VERSION 5.7 ;
BUSBITCHARS "[]" ;
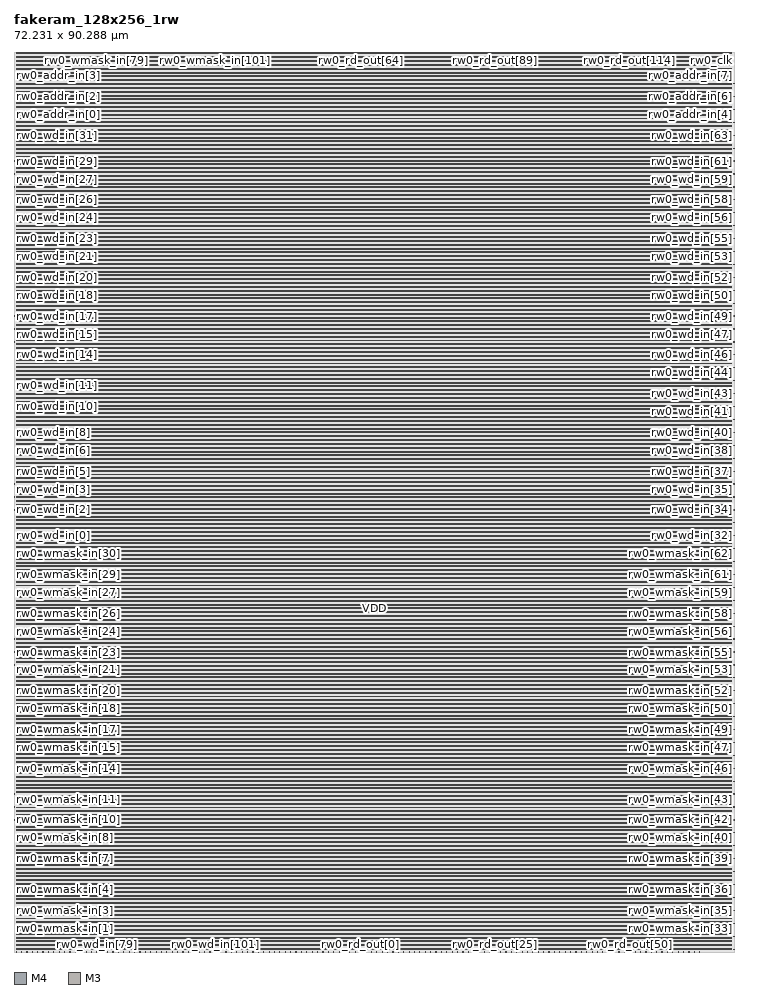
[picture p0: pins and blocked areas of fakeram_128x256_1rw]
MACRO fakeram_128x256_1rw
  FOREIGN fakeram_128x256_1rw 0 0 ;
  SYMMETRY X Y R90 ;
  SIZE 72.231 BY 90.288 ;
  CLASS BLOCK ;
  PIN rw0_wmask_in[0]
    DIRECTION INPUT ;
    USE SIGNAL ;
    SHAPE ABUTMENT ;
    PORT
      LAYER M4 ;
      RECT 0.000 0.276 0.072 0.300 ;
    END
  END rw0_wmask_in[0]
  PIN rw0_wmask_in[1]
    DIRECTION INPUT ;
    USE SIGNAL ;
    SHAPE ABUTMENT ;
    PORT
      LAYER M4 ;
      RECT 0.000 1.572 0.072 1.596 ;
    END
  END rw0_wmask_in[1]
  PIN rw0_wmask_in[2]
    DIRECTION INPUT ;
    USE SIGNAL ;
    SHAPE ABUTMENT ;
    PORT
      LAYER M4 ;
      RECT 0.000 2.868 0.072 2.892 ;
    END
  END rw0_wmask_in[2]
  PIN rw0_wmask_in[3]
    DIRECTION INPUT ;
    USE SIGNAL ;
    SHAPE ABUTMENT ;
    PORT
      LAYER M4 ;
      RECT 0.000 4.164 0.072 4.188 ;
    END
  END rw0_wmask_in[3]
  PIN rw0_wmask_in[4]
    DIRECTION INPUT ;
    USE SIGNAL ;
    SHAPE ABUTMENT ;
    PORT
      LAYER M4 ;
      RECT 0.000 5.460 0.072 5.484 ;
    END
  END rw0_wmask_in[4]
  PIN rw0_wmask_in[5]
    DIRECTION INPUT ;
    USE SIGNAL ;
    SHAPE ABUTMENT ;
    PORT
      LAYER M4 ;
      RECT 0.000 6.756 0.072 6.780 ;
    END
  END rw0_wmask_in[5]
  PIN rw0_wmask_in[6]
    DIRECTION INPUT ;
    USE SIGNAL ;
    SHAPE ABUTMENT ;
    PORT
      LAYER M4 ;
      RECT 0.000 8.052 0.072 8.076 ;
    END
  END rw0_wmask_in[6]
  PIN rw0_wmask_in[7]
    DIRECTION INPUT ;
    USE SIGNAL ;
    SHAPE ABUTMENT ;
    PORT
      LAYER M4 ;
      RECT 0.000 9.348 0.072 9.372 ;
    END
  END rw0_wmask_in[7]
  PIN rw0_wmask_in[8]
    DIRECTION INPUT ;
    USE SIGNAL ;
    SHAPE ABUTMENT ;
    PORT
      LAYER M4 ;
      RECT 0.000 10.644 0.072 10.668 ;
    END
  END rw0_wmask_in[8]
  PIN rw0_wmask_in[9]
    DIRECTION INPUT ;
    USE SIGNAL ;
    SHAPE ABUTMENT ;
    PORT
      LAYER M4 ;
      RECT 0.000 11.940 0.072 11.964 ;
    END
  END rw0_wmask_in[9]
  PIN rw0_wmask_in[10]
    DIRECTION INPUT ;
    USE SIGNAL ;
    SHAPE ABUTMENT ;
    PORT
      LAYER M4 ;
      RECT 0.000 13.236 0.072 13.260 ;
    END
  END rw0_wmask_in[10]
  PIN rw0_wmask_in[11]
    DIRECTION INPUT ;
    USE SIGNAL ;
    SHAPE ABUTMENT ;
    PORT
      LAYER M4 ;
      RECT 0.000 14.532 0.072 14.556 ;
    END
  END rw0_wmask_in[11]
  PIN rw0_wmask_in[12]
    DIRECTION INPUT ;
    USE SIGNAL ;
    SHAPE ABUTMENT ;
    PORT
      LAYER M4 ;
      RECT 0.000 15.828 0.072 15.852 ;
    END
  END rw0_wmask_in[12]
  PIN rw0_wmask_in[13]
    DIRECTION INPUT ;
    USE SIGNAL ;
    SHAPE ABUTMENT ;
    PORT
      LAYER M4 ;
      RECT 0.000 17.124 0.072 17.148 ;
    END
  END rw0_wmask_in[13]
  PIN rw0_wmask_in[14]
    DIRECTION INPUT ;
    USE SIGNAL ;
    SHAPE ABUTMENT ;
    PORT
      LAYER M4 ;
      RECT 0.000 18.420 0.072 18.444 ;
    END
  END rw0_wmask_in[14]
  PIN rw0_wmask_in[15]
    DIRECTION INPUT ;
    USE SIGNAL ;
    SHAPE ABUTMENT ;
    PORT
      LAYER M4 ;
      RECT 0.000 19.716 0.072 19.740 ;
    END
  END rw0_wmask_in[15]
  PIN rw0_wmask_in[16]
    DIRECTION INPUT ;
    USE SIGNAL ;
    SHAPE ABUTMENT ;
    PORT
      LAYER M4 ;
      RECT 0.000 21.012 0.072 21.036 ;
    END
  END rw0_wmask_in[16]
  PIN rw0_wmask_in[17]
    DIRECTION INPUT ;
    USE SIGNAL ;
    SHAPE ABUTMENT ;
    PORT
      LAYER M4 ;
      RECT 0.000 22.308 0.072 22.332 ;
    END
  END rw0_wmask_in[17]
  PIN rw0_wmask_in[18]
    DIRECTION INPUT ;
    USE SIGNAL ;
    SHAPE ABUTMENT ;
    PORT
      LAYER M4 ;
      RECT 0.000 23.604 0.072 23.628 ;
    END
  END rw0_wmask_in[18]
  PIN rw0_wmask_in[19]
    DIRECTION INPUT ;
    USE SIGNAL ;
    SHAPE ABUTMENT ;
    PORT
      LAYER M4 ;
      RECT 0.000 24.900 0.072 24.924 ;
    END
  END rw0_wmask_in[19]
  PIN rw0_wmask_in[20]
    DIRECTION INPUT ;
    USE SIGNAL ;
    SHAPE ABUTMENT ;
    PORT
      LAYER M4 ;
      RECT 0.000 26.196 0.072 26.220 ;
    END
  END rw0_wmask_in[20]
  PIN rw0_wmask_in[21]
    DIRECTION INPUT ;
    USE SIGNAL ;
    SHAPE ABUTMENT ;
    PORT
      LAYER M4 ;
      RECT 0.000 27.492 0.072 27.516 ;
    END
  END rw0_wmask_in[21]
  PIN rw0_wmask_in[22]
    DIRECTION INPUT ;
    USE SIGNAL ;
    SHAPE ABUTMENT ;
    PORT
      LAYER M4 ;
      RECT 0.000 28.788 0.072 28.812 ;
    END
  END rw0_wmask_in[22]
  PIN rw0_wmask_in[23]
    DIRECTION INPUT ;
    USE SIGNAL ;
    SHAPE ABUTMENT ;
    PORT
      LAYER M4 ;
      RECT 0.000 30.084 0.072 30.108 ;
    END
  END rw0_wmask_in[23]
  PIN rw0_wmask_in[24]
    DIRECTION INPUT ;
    USE SIGNAL ;
    SHAPE ABUTMENT ;
    PORT
      LAYER M4 ;
      RECT 0.000 31.380 0.072 31.404 ;
    END
  END rw0_wmask_in[24]
  PIN rw0_wmask_in[25]
    DIRECTION INPUT ;
    USE SIGNAL ;
    SHAPE ABUTMENT ;
    PORT
      LAYER M4 ;
      RECT 0.000 32.676 0.072 32.700 ;
    END
  END rw0_wmask_in[25]
  PIN rw0_wmask_in[26]
    DIRECTION INPUT ;
    USE SIGNAL ;
    SHAPE ABUTMENT ;
    PORT
      LAYER M4 ;
      RECT 0.000 33.972 0.072 33.996 ;
    END
  END rw0_wmask_in[26]
  PIN rw0_wmask_in[27]
    DIRECTION INPUT ;
    USE SIGNAL ;
    SHAPE ABUTMENT ;
    PORT
      LAYER M4 ;
      RECT 0.000 35.268 0.072 35.292 ;
    END
  END rw0_wmask_in[27]
  PIN rw0_wmask_in[28]
    DIRECTION INPUT ;
    USE SIGNAL ;
    SHAPE ABUTMENT ;
    PORT
      LAYER M4 ;
      RECT 0.000 36.564 0.072 36.588 ;
    END
  END rw0_wmask_in[28]
  PIN rw0_wmask_in[29]
    DIRECTION INPUT ;
    USE SIGNAL ;
    SHAPE ABUTMENT ;
    PORT
      LAYER M4 ;
      RECT 0.000 37.860 0.072 37.884 ;
    END
  END rw0_wmask_in[29]
  PIN rw0_wmask_in[30]
    DIRECTION INPUT ;
    USE SIGNAL ;
    SHAPE ABUTMENT ;
    PORT
      LAYER M4 ;
      RECT 0.000 39.156 0.072 39.180 ;
    END
  END rw0_wmask_in[30]
  PIN rw0_wmask_in[31]
    DIRECTION INPUT ;
    USE SIGNAL ;
    SHAPE ABUTMENT ;
    PORT
      LAYER M4 ;
      RECT 0.000 40.452 0.072 40.476 ;
    END
  END rw0_wmask_in[31]
  PIN rw0_wmask_in[32]
    DIRECTION INPUT ;
    USE SIGNAL ;
    SHAPE ABUTMENT ;
    PORT
      LAYER M4 ;
      RECT 72.159 0.276 72.231 0.300 ;
    END
  END rw0_wmask_in[32]
  PIN rw0_wmask_in[33]
    DIRECTION INPUT ;
    USE SIGNAL ;
    SHAPE ABUTMENT ;
    PORT
      LAYER M4 ;
      RECT 72.159 1.572 72.231 1.596 ;
    END
  END rw0_wmask_in[33]
  PIN rw0_wmask_in[34]
    DIRECTION INPUT ;
    USE SIGNAL ;
    SHAPE ABUTMENT ;
    PORT
      LAYER M4 ;
      RECT 72.159 2.868 72.231 2.892 ;
    END
  END rw0_wmask_in[34]
  PIN rw0_wmask_in[35]
    DIRECTION INPUT ;
    USE SIGNAL ;
    SHAPE ABUTMENT ;
    PORT
      LAYER M4 ;
      RECT 72.159 4.164 72.231 4.188 ;
    END
  END rw0_wmask_in[35]
  PIN rw0_wmask_in[36]
    DIRECTION INPUT ;
    USE SIGNAL ;
    SHAPE ABUTMENT ;
    PORT
      LAYER M4 ;
      RECT 72.159 5.460 72.231 5.484 ;
    END
  END rw0_wmask_in[36]
  PIN rw0_wmask_in[37]
    DIRECTION INPUT ;
    USE SIGNAL ;
    SHAPE ABUTMENT ;
    PORT
      LAYER M4 ;
      RECT 72.159 6.756 72.231 6.780 ;
    END
  END rw0_wmask_in[37]
  PIN rw0_wmask_in[38]
    DIRECTION INPUT ;
    USE SIGNAL ;
    SHAPE ABUTMENT ;
    PORT
      LAYER M4 ;
      RECT 72.159 8.052 72.231 8.076 ;
    END
  END rw0_wmask_in[38]
  PIN rw0_wmask_in[39]
    DIRECTION INPUT ;
    USE SIGNAL ;
    SHAPE ABUTMENT ;
    PORT
      LAYER M4 ;
      RECT 72.159 9.348 72.231 9.372 ;
    END
  END rw0_wmask_in[39]
  PIN rw0_wmask_in[40]
    DIRECTION INPUT ;
    USE SIGNAL ;
    SHAPE ABUTMENT ;
    PORT
      LAYER M4 ;
      RECT 72.159 10.644 72.231 10.668 ;
    END
  END rw0_wmask_in[40]
  PIN rw0_wmask_in[41]
    DIRECTION INPUT ;
    USE SIGNAL ;
    SHAPE ABUTMENT ;
    PORT
      LAYER M4 ;
      RECT 72.159 11.940 72.231 11.964 ;
    END
  END rw0_wmask_in[41]
  PIN rw0_wmask_in[42]
    DIRECTION INPUT ;
    USE SIGNAL ;
    SHAPE ABUTMENT ;
    PORT
      LAYER M4 ;
      RECT 72.159 13.236 72.231 13.260 ;
    END
  END rw0_wmask_in[42]
  PIN rw0_wmask_in[43]
    DIRECTION INPUT ;
    USE SIGNAL ;
    SHAPE ABUTMENT ;
    PORT
      LAYER M4 ;
      RECT 72.159 14.532 72.231 14.556 ;
    END
  END rw0_wmask_in[43]
  PIN rw0_wmask_in[44]
    DIRECTION INPUT ;
    USE SIGNAL ;
    SHAPE ABUTMENT ;
    PORT
      LAYER M4 ;
      RECT 72.159 15.828 72.231 15.852 ;
    END
  END rw0_wmask_in[44]
  PIN rw0_wmask_in[45]
    DIRECTION INPUT ;
    USE SIGNAL ;
    SHAPE ABUTMENT ;
    PORT
      LAYER M4 ;
      RECT 72.159 17.124 72.231 17.148 ;
    END
  END rw0_wmask_in[45]
  PIN rw0_wmask_in[46]
    DIRECTION INPUT ;
    USE SIGNAL ;
    SHAPE ABUTMENT ;
    PORT
      LAYER M4 ;
      RECT 72.159 18.420 72.231 18.444 ;
    END
  END rw0_wmask_in[46]
  PIN rw0_wmask_in[47]
    DIRECTION INPUT ;
    USE SIGNAL ;
    SHAPE ABUTMENT ;
    PORT
      LAYER M4 ;
      RECT 72.159 19.716 72.231 19.740 ;
    END
  END rw0_wmask_in[47]
  PIN rw0_wmask_in[48]
    DIRECTION INPUT ;
    USE SIGNAL ;
    SHAPE ABUTMENT ;
    PORT
      LAYER M4 ;
      RECT 72.159 21.012 72.231 21.036 ;
    END
  END rw0_wmask_in[48]
  PIN rw0_wmask_in[49]
    DIRECTION INPUT ;
    USE SIGNAL ;
    SHAPE ABUTMENT ;
    PORT
      LAYER M4 ;
      RECT 72.159 22.308 72.231 22.332 ;
    END
  END rw0_wmask_in[49]
  PIN rw0_wmask_in[50]
    DIRECTION INPUT ;
    USE SIGNAL ;
    SHAPE ABUTMENT ;
    PORT
      LAYER M4 ;
      RECT 72.159 23.604 72.231 23.628 ;
    END
  END rw0_wmask_in[50]
  PIN rw0_wmask_in[51]
    DIRECTION INPUT ;
    USE SIGNAL ;
    SHAPE ABUTMENT ;
    PORT
      LAYER M4 ;
      RECT 72.159 24.900 72.231 24.924 ;
    END
  END rw0_wmask_in[51]
  PIN rw0_wmask_in[52]
    DIRECTION INPUT ;
    USE SIGNAL ;
    SHAPE ABUTMENT ;
    PORT
      LAYER M4 ;
      RECT 72.159 26.196 72.231 26.220 ;
    END
  END rw0_wmask_in[52]
  PIN rw0_wmask_in[53]
    DIRECTION INPUT ;
    USE SIGNAL ;
    SHAPE ABUTMENT ;
    PORT
      LAYER M4 ;
      RECT 72.159 27.492 72.231 27.516 ;
    END
  END rw0_wmask_in[53]
  PIN rw0_wmask_in[54]
    DIRECTION INPUT ;
    USE SIGNAL ;
    SHAPE ABUTMENT ;
    PORT
      LAYER M4 ;
      RECT 72.159 28.788 72.231 28.812 ;
    END
  END rw0_wmask_in[54]
  PIN rw0_wmask_in[55]
    DIRECTION INPUT ;
    USE SIGNAL ;
    SHAPE ABUTMENT ;
    PORT
      LAYER M4 ;
      RECT 72.159 30.084 72.231 30.108 ;
    END
  END rw0_wmask_in[55]
  PIN rw0_wmask_in[56]
    DIRECTION INPUT ;
    USE SIGNAL ;
    SHAPE ABUTMENT ;
    PORT
      LAYER M4 ;
      RECT 72.159 31.380 72.231 31.404 ;
    END
  END rw0_wmask_in[56]
  PIN rw0_wmask_in[57]
    DIRECTION INPUT ;
    USE SIGNAL ;
    SHAPE ABUTMENT ;
    PORT
      LAYER M4 ;
      RECT 72.159 32.676 72.231 32.700 ;
    END
  END rw0_wmask_in[57]
  PIN rw0_wmask_in[58]
    DIRECTION INPUT ;
    USE SIGNAL ;
    SHAPE ABUTMENT ;
    PORT
      LAYER M4 ;
      RECT 72.159 33.972 72.231 33.996 ;
    END
  END rw0_wmask_in[58]
  PIN rw0_wmask_in[59]
    DIRECTION INPUT ;
    USE SIGNAL ;
    SHAPE ABUTMENT ;
    PORT
      LAYER M4 ;
      RECT 72.159 35.268 72.231 35.292 ;
    END
  END rw0_wmask_in[59]
  PIN rw0_wmask_in[60]
    DIRECTION INPUT ;
    USE SIGNAL ;
    SHAPE ABUTMENT ;
    PORT
      LAYER M4 ;
      RECT 72.159 36.564 72.231 36.588 ;
    END
  END rw0_wmask_in[60]
  PIN rw0_wmask_in[61]
    DIRECTION INPUT ;
    USE SIGNAL ;
    SHAPE ABUTMENT ;
    PORT
      LAYER M4 ;
      RECT 72.159 37.860 72.231 37.884 ;
    END
  END rw0_wmask_in[61]
  PIN rw0_wmask_in[62]
    DIRECTION INPUT ;
    USE SIGNAL ;
    SHAPE ABUTMENT ;
    PORT
      LAYER M4 ;
      RECT 72.159 39.156 72.231 39.180 ;
    END
  END rw0_wmask_in[62]
  PIN rw0_wmask_in[63]
    DIRECTION INPUT ;
    USE SIGNAL ;
    SHAPE ABUTMENT ;
    PORT
      LAYER M4 ;
      RECT 72.159 40.452 72.231 40.476 ;
    END
  END rw0_wmask_in[63]
  PIN rw0_wmask_in[64]
    DIRECTION INPUT ;
    USE SIGNAL ;
    SHAPE ABUTMENT ;
    PORT
      LAYER M3 ;
      RECT 0.207 90.234 0.225 90.288 ;
    END
  END rw0_wmask_in[64]
  PIN rw0_wmask_in[65]
    DIRECTION INPUT ;
    USE SIGNAL ;
    SHAPE ABUTMENT ;
    PORT
      LAYER M3 ;
      RECT 0.747 90.234 0.765 90.288 ;
    END
  END rw0_wmask_in[65]
  PIN rw0_wmask_in[66]
    DIRECTION INPUT ;
    USE SIGNAL ;
    SHAPE ABUTMENT ;
    PORT
      LAYER M3 ;
      RECT 1.287 90.234 1.305 90.288 ;
    END
  END rw0_wmask_in[66]
  PIN rw0_wmask_in[67]
    DIRECTION INPUT ;
    USE SIGNAL ;
    SHAPE ABUTMENT ;
    PORT
      LAYER M3 ;
      RECT 1.827 90.234 1.845 90.288 ;
    END
  END rw0_wmask_in[67]
  PIN rw0_wmask_in[68]
    DIRECTION INPUT ;
    USE SIGNAL ;
    SHAPE ABUTMENT ;
    PORT
      LAYER M3 ;
      RECT 2.367 90.234 2.385 90.288 ;
    END
  END rw0_wmask_in[68]
  PIN rw0_wmask_in[69]
    DIRECTION INPUT ;
    USE SIGNAL ;
    SHAPE ABUTMENT ;
    PORT
      LAYER M3 ;
      RECT 2.907 90.234 2.925 90.288 ;
    END
  END rw0_wmask_in[69]
  PIN rw0_wmask_in[70]
    DIRECTION INPUT ;
    USE SIGNAL ;
    SHAPE ABUTMENT ;
    PORT
      LAYER M3 ;
      RECT 3.447 90.234 3.465 90.288 ;
    END
  END rw0_wmask_in[70]
  PIN rw0_wmask_in[71]
    DIRECTION INPUT ;
    USE SIGNAL ;
    SHAPE ABUTMENT ;
    PORT
      LAYER M3 ;
      RECT 3.987 90.234 4.005 90.288 ;
    END
  END rw0_wmask_in[71]
  PIN rw0_wmask_in[72]
    DIRECTION INPUT ;
    USE SIGNAL ;
    SHAPE ABUTMENT ;
    PORT
      LAYER M3 ;
      RECT 4.527 90.234 4.545 90.288 ;
    END
  END rw0_wmask_in[72]
  PIN rw0_wmask_in[73]
    DIRECTION INPUT ;
    USE SIGNAL ;
    SHAPE ABUTMENT ;
    PORT
      LAYER M3 ;
      RECT 5.067 90.234 5.085 90.288 ;
    END
  END rw0_wmask_in[73]
  PIN rw0_wmask_in[74]
    DIRECTION INPUT ;
    USE SIGNAL ;
    SHAPE ABUTMENT ;
    PORT
      LAYER M3 ;
      RECT 5.607 90.234 5.625 90.288 ;
    END
  END rw0_wmask_in[74]
  PIN rw0_wmask_in[75]
    DIRECTION INPUT ;
    USE SIGNAL ;
    SHAPE ABUTMENT ;
    PORT
      LAYER M3 ;
      RECT 6.147 90.234 6.165 90.288 ;
    END
  END rw0_wmask_in[75]
  PIN rw0_wmask_in[76]
    DIRECTION INPUT ;
    USE SIGNAL ;
    SHAPE ABUTMENT ;
    PORT
      LAYER M3 ;
      RECT 6.687 90.234 6.705 90.288 ;
    END
  END rw0_wmask_in[76]
  PIN rw0_wmask_in[77]
    DIRECTION INPUT ;
    USE SIGNAL ;
    SHAPE ABUTMENT ;
    PORT
      LAYER M3 ;
      RECT 7.227 90.234 7.245 90.288 ;
    END
  END rw0_wmask_in[77]
  PIN rw0_wmask_in[78]
    DIRECTION INPUT ;
    USE SIGNAL ;
    SHAPE ABUTMENT ;
    PORT
      LAYER M3 ;
      RECT 7.767 90.234 7.785 90.288 ;
    END
  END rw0_wmask_in[78]
  PIN rw0_wmask_in[79]
    DIRECTION INPUT ;
    USE SIGNAL ;
    SHAPE ABUTMENT ;
    PORT
      LAYER M3 ;
      RECT 8.307 90.234 8.325 90.288 ;
    END
  END rw0_wmask_in[79]
  PIN rw0_wmask_in[80]
    DIRECTION INPUT ;
    USE SIGNAL ;
    SHAPE ABUTMENT ;
    PORT
      LAYER M3 ;
      RECT 8.847 90.234 8.865 90.288 ;
    END
  END rw0_wmask_in[80]
  PIN rw0_wmask_in[81]
    DIRECTION INPUT ;
    USE SIGNAL ;
    SHAPE ABUTMENT ;
    PORT
      LAYER M3 ;
      RECT 9.387 90.234 9.405 90.288 ;
    END
  END rw0_wmask_in[81]
  PIN rw0_wmask_in[82]
    DIRECTION INPUT ;
    USE SIGNAL ;
    SHAPE ABUTMENT ;
    PORT
      LAYER M3 ;
      RECT 9.927 90.234 9.945 90.288 ;
    END
  END rw0_wmask_in[82]
  PIN rw0_wmask_in[83]
    DIRECTION INPUT ;
    USE SIGNAL ;
    SHAPE ABUTMENT ;
    PORT
      LAYER M3 ;
      RECT 10.467 90.234 10.485 90.288 ;
    END
  END rw0_wmask_in[83]
  PIN rw0_wmask_in[84]
    DIRECTION INPUT ;
    USE SIGNAL ;
    SHAPE ABUTMENT ;
    PORT
      LAYER M3 ;
      RECT 11.007 90.234 11.025 90.288 ;
    END
  END rw0_wmask_in[84]
  PIN rw0_wmask_in[85]
    DIRECTION INPUT ;
    USE SIGNAL ;
    SHAPE ABUTMENT ;
    PORT
      LAYER M3 ;
      RECT 11.547 90.234 11.565 90.288 ;
    END
  END rw0_wmask_in[85]
  PIN rw0_wmask_in[86]
    DIRECTION INPUT ;
    USE SIGNAL ;
    SHAPE ABUTMENT ;
    PORT
      LAYER M3 ;
      RECT 12.087 90.234 12.105 90.288 ;
    END
  END rw0_wmask_in[86]
  PIN rw0_wmask_in[87]
    DIRECTION INPUT ;
    USE SIGNAL ;
    SHAPE ABUTMENT ;
    PORT
      LAYER M3 ;
      RECT 12.627 90.234 12.645 90.288 ;
    END
  END rw0_wmask_in[87]
  PIN rw0_wmask_in[88]
    DIRECTION INPUT ;
    USE SIGNAL ;
    SHAPE ABUTMENT ;
    PORT
      LAYER M3 ;
      RECT 13.167 90.234 13.185 90.288 ;
    END
  END rw0_wmask_in[88]
  PIN rw0_wmask_in[89]
    DIRECTION INPUT ;
    USE SIGNAL ;
    SHAPE ABUTMENT ;
    PORT
      LAYER M3 ;
      RECT 13.707 90.234 13.725 90.288 ;
    END
  END rw0_wmask_in[89]
  PIN rw0_wmask_in[90]
    DIRECTION INPUT ;
    USE SIGNAL ;
    SHAPE ABUTMENT ;
    PORT
      LAYER M3 ;
      RECT 14.247 90.234 14.265 90.288 ;
    END
  END rw0_wmask_in[90]
  PIN rw0_wmask_in[91]
    DIRECTION INPUT ;
    USE SIGNAL ;
    SHAPE ABUTMENT ;
    PORT
      LAYER M3 ;
      RECT 14.787 90.234 14.805 90.288 ;
    END
  END rw0_wmask_in[91]
  PIN rw0_wmask_in[92]
    DIRECTION INPUT ;
    USE SIGNAL ;
    SHAPE ABUTMENT ;
    PORT
      LAYER M3 ;
      RECT 15.327 90.234 15.345 90.288 ;
    END
  END rw0_wmask_in[92]
  PIN rw0_wmask_in[93]
    DIRECTION INPUT ;
    USE SIGNAL ;
    SHAPE ABUTMENT ;
    PORT
      LAYER M3 ;
      RECT 15.867 90.234 15.885 90.288 ;
    END
  END rw0_wmask_in[93]
  PIN rw0_wmask_in[94]
    DIRECTION INPUT ;
    USE SIGNAL ;
    SHAPE ABUTMENT ;
    PORT
      LAYER M3 ;
      RECT 16.407 90.234 16.425 90.288 ;
    END
  END rw0_wmask_in[94]
  PIN rw0_wmask_in[95]
    DIRECTION INPUT ;
    USE SIGNAL ;
    SHAPE ABUTMENT ;
    PORT
      LAYER M3 ;
      RECT 16.947 90.234 16.965 90.288 ;
    END
  END rw0_wmask_in[95]
  PIN rw0_wmask_in[96]
    DIRECTION INPUT ;
    USE SIGNAL ;
    SHAPE ABUTMENT ;
    PORT
      LAYER M3 ;
      RECT 17.487 90.234 17.505 90.288 ;
    END
  END rw0_wmask_in[96]
  PIN rw0_wmask_in[97]
    DIRECTION INPUT ;
    USE SIGNAL ;
    SHAPE ABUTMENT ;
    PORT
      LAYER M3 ;
      RECT 18.027 90.234 18.045 90.288 ;
    END
  END rw0_wmask_in[97]
  PIN rw0_wmask_in[98]
    DIRECTION INPUT ;
    USE SIGNAL ;
    SHAPE ABUTMENT ;
    PORT
      LAYER M3 ;
      RECT 18.567 90.234 18.585 90.288 ;
    END
  END rw0_wmask_in[98]
  PIN rw0_wmask_in[99]
    DIRECTION INPUT ;
    USE SIGNAL ;
    SHAPE ABUTMENT ;
    PORT
      LAYER M3 ;
      RECT 19.107 90.234 19.125 90.288 ;
    END
  END rw0_wmask_in[99]
  PIN rw0_wmask_in[100]
    DIRECTION INPUT ;
    USE SIGNAL ;
    SHAPE ABUTMENT ;
    PORT
      LAYER M3 ;
      RECT 19.647 90.234 19.665 90.288 ;
    END
  END rw0_wmask_in[100]
  PIN rw0_wmask_in[101]
    DIRECTION INPUT ;
    USE SIGNAL ;
    SHAPE ABUTMENT ;
    PORT
      LAYER M3 ;
      RECT 20.187 90.234 20.205 90.288 ;
    END
  END rw0_wmask_in[101]
  PIN rw0_wmask_in[102]
    DIRECTION INPUT ;
    USE SIGNAL ;
    SHAPE ABUTMENT ;
    PORT
      LAYER M3 ;
      RECT 20.727 90.234 20.745 90.288 ;
    END
  END rw0_wmask_in[102]
  PIN rw0_wmask_in[103]
    DIRECTION INPUT ;
    USE SIGNAL ;
    SHAPE ABUTMENT ;
    PORT
      LAYER M3 ;
      RECT 21.267 90.234 21.285 90.288 ;
    END
  END rw0_wmask_in[103]
  PIN rw0_wmask_in[104]
    DIRECTION INPUT ;
    USE SIGNAL ;
    SHAPE ABUTMENT ;
    PORT
      LAYER M3 ;
      RECT 21.807 90.234 21.825 90.288 ;
    END
  END rw0_wmask_in[104]
  PIN rw0_wmask_in[105]
    DIRECTION INPUT ;
    USE SIGNAL ;
    SHAPE ABUTMENT ;
    PORT
      LAYER M3 ;
      RECT 22.347 90.234 22.365 90.288 ;
    END
  END rw0_wmask_in[105]
  PIN rw0_wmask_in[106]
    DIRECTION INPUT ;
    USE SIGNAL ;
    SHAPE ABUTMENT ;
    PORT
      LAYER M3 ;
      RECT 22.887 90.234 22.905 90.288 ;
    END
  END rw0_wmask_in[106]
  PIN rw0_wmask_in[107]
    DIRECTION INPUT ;
    USE SIGNAL ;
    SHAPE ABUTMENT ;
    PORT
      LAYER M3 ;
      RECT 23.427 90.234 23.445 90.288 ;
    END
  END rw0_wmask_in[107]
  PIN rw0_wmask_in[108]
    DIRECTION INPUT ;
    USE SIGNAL ;
    SHAPE ABUTMENT ;
    PORT
      LAYER M3 ;
      RECT 23.967 90.234 23.985 90.288 ;
    END
  END rw0_wmask_in[108]
  PIN rw0_wmask_in[109]
    DIRECTION INPUT ;
    USE SIGNAL ;
    SHAPE ABUTMENT ;
    PORT
      LAYER M3 ;
      RECT 24.507 90.234 24.525 90.288 ;
    END
  END rw0_wmask_in[109]
  PIN rw0_wmask_in[110]
    DIRECTION INPUT ;
    USE SIGNAL ;
    SHAPE ABUTMENT ;
    PORT
      LAYER M3 ;
      RECT 25.047 90.234 25.065 90.288 ;
    END
  END rw0_wmask_in[110]
  PIN rw0_wmask_in[111]
    DIRECTION INPUT ;
    USE SIGNAL ;
    SHAPE ABUTMENT ;
    PORT
      LAYER M3 ;
      RECT 25.587 90.234 25.605 90.288 ;
    END
  END rw0_wmask_in[111]
  PIN rw0_wmask_in[112]
    DIRECTION INPUT ;
    USE SIGNAL ;
    SHAPE ABUTMENT ;
    PORT
      LAYER M3 ;
      RECT 26.127 90.234 26.145 90.288 ;
    END
  END rw0_wmask_in[112]
  PIN rw0_wmask_in[113]
    DIRECTION INPUT ;
    USE SIGNAL ;
    SHAPE ABUTMENT ;
    PORT
      LAYER M3 ;
      RECT 26.667 90.234 26.685 90.288 ;
    END
  END rw0_wmask_in[113]
  PIN rw0_wmask_in[114]
    DIRECTION INPUT ;
    USE SIGNAL ;
    SHAPE ABUTMENT ;
    PORT
      LAYER M3 ;
      RECT 27.207 90.234 27.225 90.288 ;
    END
  END rw0_wmask_in[114]
  PIN rw0_wmask_in[115]
    DIRECTION INPUT ;
    USE SIGNAL ;
    SHAPE ABUTMENT ;
    PORT
      LAYER M3 ;
      RECT 27.747 90.234 27.765 90.288 ;
    END
  END rw0_wmask_in[115]
  PIN rw0_wmask_in[116]
    DIRECTION INPUT ;
    USE SIGNAL ;
    SHAPE ABUTMENT ;
    PORT
      LAYER M3 ;
      RECT 28.287 90.234 28.305 90.288 ;
    END
  END rw0_wmask_in[116]
  PIN rw0_wmask_in[117]
    DIRECTION INPUT ;
    USE SIGNAL ;
    SHAPE ABUTMENT ;
    PORT
      LAYER M3 ;
      RECT 28.827 90.234 28.845 90.288 ;
    END
  END rw0_wmask_in[117]
  PIN rw0_wmask_in[118]
    DIRECTION INPUT ;
    USE SIGNAL ;
    SHAPE ABUTMENT ;
    PORT
      LAYER M3 ;
      RECT 29.367 90.234 29.385 90.288 ;
    END
  END rw0_wmask_in[118]
  PIN rw0_wmask_in[119]
    DIRECTION INPUT ;
    USE SIGNAL ;
    SHAPE ABUTMENT ;
    PORT
      LAYER M3 ;
      RECT 29.907 90.234 29.925 90.288 ;
    END
  END rw0_wmask_in[119]
  PIN rw0_wmask_in[120]
    DIRECTION INPUT ;
    USE SIGNAL ;
    SHAPE ABUTMENT ;
    PORT
      LAYER M3 ;
      RECT 30.447 90.234 30.465 90.288 ;
    END
  END rw0_wmask_in[120]
  PIN rw0_wmask_in[121]
    DIRECTION INPUT ;
    USE SIGNAL ;
    SHAPE ABUTMENT ;
    PORT
      LAYER M3 ;
      RECT 30.987 90.234 31.005 90.288 ;
    END
  END rw0_wmask_in[121]
  PIN rw0_wmask_in[122]
    DIRECTION INPUT ;
    USE SIGNAL ;
    SHAPE ABUTMENT ;
    PORT
      LAYER M3 ;
      RECT 31.527 90.234 31.545 90.288 ;
    END
  END rw0_wmask_in[122]
  PIN rw0_wmask_in[123]
    DIRECTION INPUT ;
    USE SIGNAL ;
    SHAPE ABUTMENT ;
    PORT
      LAYER M3 ;
      RECT 32.067 90.234 32.085 90.288 ;
    END
  END rw0_wmask_in[123]
  PIN rw0_wmask_in[124]
    DIRECTION INPUT ;
    USE SIGNAL ;
    SHAPE ABUTMENT ;
    PORT
      LAYER M3 ;
      RECT 32.607 90.234 32.625 90.288 ;
    END
  END rw0_wmask_in[124]
  PIN rw0_wmask_in[125]
    DIRECTION INPUT ;
    USE SIGNAL ;
    SHAPE ABUTMENT ;
    PORT
      LAYER M3 ;
      RECT 33.147 90.234 33.165 90.288 ;
    END
  END rw0_wmask_in[125]
  PIN rw0_wmask_in[126]
    DIRECTION INPUT ;
    USE SIGNAL ;
    SHAPE ABUTMENT ;
    PORT
      LAYER M3 ;
      RECT 33.687 90.234 33.705 90.288 ;
    END
  END rw0_wmask_in[126]
  PIN rw0_wmask_in[127]
    DIRECTION INPUT ;
    USE SIGNAL ;
    SHAPE ABUTMENT ;
    PORT
      LAYER M3 ;
      RECT 34.227 90.234 34.245 90.288 ;
    END
  END rw0_wmask_in[127]
  PIN rw0_wd_in[0]
    DIRECTION INPUT ;
    USE SIGNAL ;
    SHAPE ABUTMENT ;
    PORT
      LAYER M4 ;
      RECT 0.000 41.748 0.072 41.772 ;
    END
  END rw0_wd_in[0]
  PIN rw0_wd_in[1]
    DIRECTION INPUT ;
    USE SIGNAL ;
    SHAPE ABUTMENT ;
    PORT
      LAYER M4 ;
      RECT 0.000 43.044 0.072 43.068 ;
    END
  END rw0_wd_in[1]
  PIN rw0_wd_in[2]
    DIRECTION INPUT ;
    USE SIGNAL ;
    SHAPE ABUTMENT ;
    PORT
      LAYER M4 ;
      RECT 0.000 44.340 0.072 44.364 ;
    END
  END rw0_wd_in[2]
  PIN rw0_wd_in[3]
    DIRECTION INPUT ;
    USE SIGNAL ;
    SHAPE ABUTMENT ;
    PORT
      LAYER M4 ;
      RECT 0.000 45.636 0.072 45.660 ;
    END
  END rw0_wd_in[3]
  PIN rw0_wd_in[4]
    DIRECTION INPUT ;
    USE SIGNAL ;
    SHAPE ABUTMENT ;
    PORT
      LAYER M4 ;
      RECT 0.000 46.932 0.072 46.956 ;
    END
  END rw0_wd_in[4]
  PIN rw0_wd_in[5]
    DIRECTION INPUT ;
    USE SIGNAL ;
    SHAPE ABUTMENT ;
    PORT
      LAYER M4 ;
      RECT 0.000 48.228 0.072 48.252 ;
    END
  END rw0_wd_in[5]
  PIN rw0_wd_in[6]
    DIRECTION INPUT ;
    USE SIGNAL ;
    SHAPE ABUTMENT ;
    PORT
      LAYER M4 ;
      RECT 0.000 49.524 0.072 49.548 ;
    END
  END rw0_wd_in[6]
  PIN rw0_wd_in[7]
    DIRECTION INPUT ;
    USE SIGNAL ;
    SHAPE ABUTMENT ;
    PORT
      LAYER M4 ;
      RECT 0.000 50.820 0.072 50.844 ;
    END
  END rw0_wd_in[7]
  PIN rw0_wd_in[8]
    DIRECTION INPUT ;
    USE SIGNAL ;
    SHAPE ABUTMENT ;
    PORT
      LAYER M4 ;
      RECT 0.000 52.116 0.072 52.140 ;
    END
  END rw0_wd_in[8]
  PIN rw0_wd_in[9]
    DIRECTION INPUT ;
    USE SIGNAL ;
    SHAPE ABUTMENT ;
    PORT
      LAYER M4 ;
      RECT 0.000 53.412 0.072 53.436 ;
    END
  END rw0_wd_in[9]
  PIN rw0_wd_in[10]
    DIRECTION INPUT ;
    USE SIGNAL ;
    SHAPE ABUTMENT ;
    PORT
      LAYER M4 ;
      RECT 0.000 54.708 0.072 54.732 ;
    END
  END rw0_wd_in[10]
  PIN rw0_wd_in[11]
    DIRECTION INPUT ;
    USE SIGNAL ;
    SHAPE ABUTMENT ;
    PORT
      LAYER M4 ;
      RECT 0.000 56.004 0.072 56.028 ;
    END
  END rw0_wd_in[11]
  PIN rw0_wd_in[12]
    DIRECTION INPUT ;
    USE SIGNAL ;
    SHAPE ABUTMENT ;
    PORT
      LAYER M4 ;
      RECT 0.000 57.300 0.072 57.324 ;
    END
  END rw0_wd_in[12]
  PIN rw0_wd_in[13]
    DIRECTION INPUT ;
    USE SIGNAL ;
    SHAPE ABUTMENT ;
    PORT
      LAYER M4 ;
      RECT 0.000 58.596 0.072 58.620 ;
    END
  END rw0_wd_in[13]
  PIN rw0_wd_in[14]
    DIRECTION INPUT ;
    USE SIGNAL ;
    SHAPE ABUTMENT ;
    PORT
      LAYER M4 ;
      RECT 0.000 59.892 0.072 59.916 ;
    END
  END rw0_wd_in[14]
  PIN rw0_wd_in[15]
    DIRECTION INPUT ;
    USE SIGNAL ;
    SHAPE ABUTMENT ;
    PORT
      LAYER M4 ;
      RECT 0.000 61.188 0.072 61.212 ;
    END
  END rw0_wd_in[15]
  PIN rw0_wd_in[16]
    DIRECTION INPUT ;
    USE SIGNAL ;
    SHAPE ABUTMENT ;
    PORT
      LAYER M4 ;
      RECT 0.000 62.484 0.072 62.508 ;
    END
  END rw0_wd_in[16]
  PIN rw0_wd_in[17]
    DIRECTION INPUT ;
    USE SIGNAL ;
    SHAPE ABUTMENT ;
    PORT
      LAYER M4 ;
      RECT 0.000 63.780 0.072 63.804 ;
    END
  END rw0_wd_in[17]
  PIN rw0_wd_in[18]
    DIRECTION INPUT ;
    USE SIGNAL ;
    SHAPE ABUTMENT ;
    PORT
      LAYER M4 ;
      RECT 0.000 65.076 0.072 65.100 ;
    END
  END rw0_wd_in[18]
  PIN rw0_wd_in[19]
    DIRECTION INPUT ;
    USE SIGNAL ;
    SHAPE ABUTMENT ;
    PORT
      LAYER M4 ;
      RECT 0.000 66.372 0.072 66.396 ;
    END
  END rw0_wd_in[19]
  PIN rw0_wd_in[20]
    DIRECTION INPUT ;
    USE SIGNAL ;
    SHAPE ABUTMENT ;
    PORT
      LAYER M4 ;
      RECT 0.000 67.668 0.072 67.692 ;
    END
  END rw0_wd_in[20]
  PIN rw0_wd_in[21]
    DIRECTION INPUT ;
    USE SIGNAL ;
    SHAPE ABUTMENT ;
    PORT
      LAYER M4 ;
      RECT 0.000 68.964 0.072 68.988 ;
    END
  END rw0_wd_in[21]
  PIN rw0_wd_in[22]
    DIRECTION INPUT ;
    USE SIGNAL ;
    SHAPE ABUTMENT ;
    PORT
      LAYER M4 ;
      RECT 0.000 70.260 0.072 70.284 ;
    END
  END rw0_wd_in[22]
  PIN rw0_wd_in[23]
    DIRECTION INPUT ;
    USE SIGNAL ;
    SHAPE ABUTMENT ;
    PORT
      LAYER M4 ;
      RECT 0.000 71.556 0.072 71.580 ;
    END
  END rw0_wd_in[23]
  PIN rw0_wd_in[24]
    DIRECTION INPUT ;
    USE SIGNAL ;
    SHAPE ABUTMENT ;
    PORT
      LAYER M4 ;
      RECT 0.000 72.852 0.072 72.876 ;
    END
  END rw0_wd_in[24]
  PIN rw0_wd_in[25]
    DIRECTION INPUT ;
    USE SIGNAL ;
    SHAPE ABUTMENT ;
    PORT
      LAYER M4 ;
      RECT 0.000 74.148 0.072 74.172 ;
    END
  END rw0_wd_in[25]
  PIN rw0_wd_in[26]
    DIRECTION INPUT ;
    USE SIGNAL ;
    SHAPE ABUTMENT ;
    PORT
      LAYER M4 ;
      RECT 0.000 75.444 0.072 75.468 ;
    END
  END rw0_wd_in[26]
  PIN rw0_wd_in[27]
    DIRECTION INPUT ;
    USE SIGNAL ;
    SHAPE ABUTMENT ;
    PORT
      LAYER M4 ;
      RECT 0.000 76.740 0.072 76.764 ;
    END
  END rw0_wd_in[27]
  PIN rw0_wd_in[28]
    DIRECTION INPUT ;
    USE SIGNAL ;
    SHAPE ABUTMENT ;
    PORT
      LAYER M4 ;
      RECT 0.000 78.036 0.072 78.060 ;
    END
  END rw0_wd_in[28]
  PIN rw0_wd_in[29]
    DIRECTION INPUT ;
    USE SIGNAL ;
    SHAPE ABUTMENT ;
    PORT
      LAYER M4 ;
      RECT 0.000 79.332 0.072 79.356 ;
    END
  END rw0_wd_in[29]
  PIN rw0_wd_in[30]
    DIRECTION INPUT ;
    USE SIGNAL ;
    SHAPE ABUTMENT ;
    PORT
      LAYER M4 ;
      RECT 0.000 80.628 0.072 80.652 ;
    END
  END rw0_wd_in[30]
  PIN rw0_wd_in[31]
    DIRECTION INPUT ;
    USE SIGNAL ;
    SHAPE ABUTMENT ;
    PORT
      LAYER M4 ;
      RECT 0.000 81.924 0.072 81.948 ;
    END
  END rw0_wd_in[31]
  PIN rw0_wd_in[32]
    DIRECTION INPUT ;
    USE SIGNAL ;
    SHAPE ABUTMENT ;
    PORT
      LAYER M4 ;
      RECT 72.159 41.748 72.231 41.772 ;
    END
  END rw0_wd_in[32]
  PIN rw0_wd_in[33]
    DIRECTION INPUT ;
    USE SIGNAL ;
    SHAPE ABUTMENT ;
    PORT
      LAYER M4 ;
      RECT 72.159 43.044 72.231 43.068 ;
    END
  END rw0_wd_in[33]
  PIN rw0_wd_in[34]
    DIRECTION INPUT ;
    USE SIGNAL ;
    SHAPE ABUTMENT ;
    PORT
      LAYER M4 ;
      RECT 72.159 44.340 72.231 44.364 ;
    END
  END rw0_wd_in[34]
  PIN rw0_wd_in[35]
    DIRECTION INPUT ;
    USE SIGNAL ;
    SHAPE ABUTMENT ;
    PORT
      LAYER M4 ;
      RECT 72.159 45.636 72.231 45.660 ;
    END
  END rw0_wd_in[35]
  PIN rw0_wd_in[36]
    DIRECTION INPUT ;
    USE SIGNAL ;
    SHAPE ABUTMENT ;
    PORT
      LAYER M4 ;
      RECT 72.159 46.932 72.231 46.956 ;
    END
  END rw0_wd_in[36]
  PIN rw0_wd_in[37]
    DIRECTION INPUT ;
    USE SIGNAL ;
    SHAPE ABUTMENT ;
    PORT
      LAYER M4 ;
      RECT 72.159 48.228 72.231 48.252 ;
    END
  END rw0_wd_in[37]
  PIN rw0_wd_in[38]
    DIRECTION INPUT ;
    USE SIGNAL ;
    SHAPE ABUTMENT ;
    PORT
      LAYER M4 ;
      RECT 72.159 49.524 72.231 49.548 ;
    END
  END rw0_wd_in[38]
  PIN rw0_wd_in[39]
    DIRECTION INPUT ;
    USE SIGNAL ;
    SHAPE ABUTMENT ;
    PORT
      LAYER M4 ;
      RECT 72.159 50.820 72.231 50.844 ;
    END
  END rw0_wd_in[39]
  PIN rw0_wd_in[40]
    DIRECTION INPUT ;
    USE SIGNAL ;
    SHAPE ABUTMENT ;
    PORT
      LAYER M4 ;
      RECT 72.159 52.116 72.231 52.140 ;
    END
  END rw0_wd_in[40]
  PIN rw0_wd_in[41]
    DIRECTION INPUT ;
    USE SIGNAL ;
    SHAPE ABUTMENT ;
    PORT
      LAYER M4 ;
      RECT 72.159 53.412 72.231 53.436 ;
    END
  END rw0_wd_in[41]
  PIN rw0_wd_in[42]
    DIRECTION INPUT ;
    USE SIGNAL ;
    SHAPE ABUTMENT ;
    PORT
      LAYER M4 ;
      RECT 72.159 54.708 72.231 54.732 ;
    END
  END rw0_wd_in[42]
  PIN rw0_wd_in[43]
    DIRECTION INPUT ;
    USE SIGNAL ;
    SHAPE ABUTMENT ;
    PORT
      LAYER M4 ;
      RECT 72.159 56.004 72.231 56.028 ;
    END
  END rw0_wd_in[43]
  PIN rw0_wd_in[44]
    DIRECTION INPUT ;
    USE SIGNAL ;
    SHAPE ABUTMENT ;
    PORT
      LAYER M4 ;
      RECT 72.159 57.300 72.231 57.324 ;
    END
  END rw0_wd_in[44]
  PIN rw0_wd_in[45]
    DIRECTION INPUT ;
    USE SIGNAL ;
    SHAPE ABUTMENT ;
    PORT
      LAYER M4 ;
      RECT 72.159 58.596 72.231 58.620 ;
    END
  END rw0_wd_in[45]
  PIN rw0_wd_in[46]
    DIRECTION INPUT ;
    USE SIGNAL ;
    SHAPE ABUTMENT ;
    PORT
      LAYER M4 ;
      RECT 72.159 59.892 72.231 59.916 ;
    END
  END rw0_wd_in[46]
  PIN rw0_wd_in[47]
    DIRECTION INPUT ;
    USE SIGNAL ;
    SHAPE ABUTMENT ;
    PORT
      LAYER M4 ;
      RECT 72.159 61.188 72.231 61.212 ;
    END
  END rw0_wd_in[47]
  PIN rw0_wd_in[48]
    DIRECTION INPUT ;
    USE SIGNAL ;
    SHAPE ABUTMENT ;
    PORT
      LAYER M4 ;
      RECT 72.159 62.484 72.231 62.508 ;
    END
  END rw0_wd_in[48]
  PIN rw0_wd_in[49]
    DIRECTION INPUT ;
    USE SIGNAL ;
    SHAPE ABUTMENT ;
    PORT
      LAYER M4 ;
      RECT 72.159 63.780 72.231 63.804 ;
    END
  END rw0_wd_in[49]
  PIN rw0_wd_in[50]
    DIRECTION INPUT ;
    USE SIGNAL ;
    SHAPE ABUTMENT ;
    PORT
      LAYER M4 ;
      RECT 72.159 65.076 72.231 65.100 ;
    END
  END rw0_wd_in[50]
  PIN rw0_wd_in[51]
    DIRECTION INPUT ;
    USE SIGNAL ;
    SHAPE ABUTMENT ;
    PORT
      LAYER M4 ;
      RECT 72.159 66.372 72.231 66.396 ;
    END
  END rw0_wd_in[51]
  PIN rw0_wd_in[52]
    DIRECTION INPUT ;
    USE SIGNAL ;
    SHAPE ABUTMENT ;
    PORT
      LAYER M4 ;
      RECT 72.159 67.668 72.231 67.692 ;
    END
  END rw0_wd_in[52]
  PIN rw0_wd_in[53]
    DIRECTION INPUT ;
    USE SIGNAL ;
    SHAPE ABUTMENT ;
    PORT
      LAYER M4 ;
      RECT 72.159 68.964 72.231 68.988 ;
    END
  END rw0_wd_in[53]
  PIN rw0_wd_in[54]
    DIRECTION INPUT ;
    USE SIGNAL ;
    SHAPE ABUTMENT ;
    PORT
      LAYER M4 ;
      RECT 72.159 70.260 72.231 70.284 ;
    END
  END rw0_wd_in[54]
  PIN rw0_wd_in[55]
    DIRECTION INPUT ;
    USE SIGNAL ;
    SHAPE ABUTMENT ;
    PORT
      LAYER M4 ;
      RECT 72.159 71.556 72.231 71.580 ;
    END
  END rw0_wd_in[55]
  PIN rw0_wd_in[56]
    DIRECTION INPUT ;
    USE SIGNAL ;
    SHAPE ABUTMENT ;
    PORT
      LAYER M4 ;
      RECT 72.159 72.852 72.231 72.876 ;
    END
  END rw0_wd_in[56]
  PIN rw0_wd_in[57]
    DIRECTION INPUT ;
    USE SIGNAL ;
    SHAPE ABUTMENT ;
    PORT
      LAYER M4 ;
      RECT 72.159 74.148 72.231 74.172 ;
    END
  END rw0_wd_in[57]
  PIN rw0_wd_in[58]
    DIRECTION INPUT ;
    USE SIGNAL ;
    SHAPE ABUTMENT ;
    PORT
      LAYER M4 ;
      RECT 72.159 75.444 72.231 75.468 ;
    END
  END rw0_wd_in[58]
  PIN rw0_wd_in[59]
    DIRECTION INPUT ;
    USE SIGNAL ;
    SHAPE ABUTMENT ;
    PORT
      LAYER M4 ;
      RECT 72.159 76.740 72.231 76.764 ;
    END
  END rw0_wd_in[59]
  PIN rw0_wd_in[60]
    DIRECTION INPUT ;
    USE SIGNAL ;
    SHAPE ABUTMENT ;
    PORT
      LAYER M4 ;
      RECT 72.159 78.036 72.231 78.060 ;
    END
  END rw0_wd_in[60]
  PIN rw0_wd_in[61]
    DIRECTION INPUT ;
    USE SIGNAL ;
    SHAPE ABUTMENT ;
    PORT
      LAYER M4 ;
      RECT 72.159 79.332 72.231 79.356 ;
    END
  END rw0_wd_in[61]
  PIN rw0_wd_in[62]
    DIRECTION INPUT ;
    USE SIGNAL ;
    SHAPE ABUTMENT ;
    PORT
      LAYER M4 ;
      RECT 72.159 80.628 72.231 80.652 ;
    END
  END rw0_wd_in[62]
  PIN rw0_wd_in[63]
    DIRECTION INPUT ;
    USE SIGNAL ;
    SHAPE ABUTMENT ;
    PORT
      LAYER M4 ;
      RECT 72.159 81.924 72.231 81.948 ;
    END
  END rw0_wd_in[63]
  PIN rw0_wd_in[64]
    DIRECTION INPUT ;
    USE SIGNAL ;
    SHAPE ABUTMENT ;
    PORT
      LAYER M3 ;
      RECT 0.207 0.000 0.225 0.054 ;
    END
  END rw0_wd_in[64]
  PIN rw0_wd_in[65]
    DIRECTION INPUT ;
    USE SIGNAL ;
    SHAPE ABUTMENT ;
    PORT
      LAYER M3 ;
      RECT 0.747 0.000 0.765 0.054 ;
    END
  END rw0_wd_in[65]
  PIN rw0_wd_in[66]
    DIRECTION INPUT ;
    USE SIGNAL ;
    SHAPE ABUTMENT ;
    PORT
      LAYER M3 ;
      RECT 1.287 0.000 1.305 0.054 ;
    END
  END rw0_wd_in[66]
  PIN rw0_wd_in[67]
    DIRECTION INPUT ;
    USE SIGNAL ;
    SHAPE ABUTMENT ;
    PORT
      LAYER M3 ;
      RECT 1.827 0.000 1.845 0.054 ;
    END
  END rw0_wd_in[67]
  PIN rw0_wd_in[68]
    DIRECTION INPUT ;
    USE SIGNAL ;
    SHAPE ABUTMENT ;
    PORT
      LAYER M3 ;
      RECT 2.367 0.000 2.385 0.054 ;
    END
  END rw0_wd_in[68]
  PIN rw0_wd_in[69]
    DIRECTION INPUT ;
    USE SIGNAL ;
    SHAPE ABUTMENT ;
    PORT
      LAYER M3 ;
      RECT 2.907 0.000 2.925 0.054 ;
    END
  END rw0_wd_in[69]
  PIN rw0_wd_in[70]
    DIRECTION INPUT ;
    USE SIGNAL ;
    SHAPE ABUTMENT ;
    PORT
      LAYER M3 ;
      RECT 3.447 0.000 3.465 0.054 ;
    END
  END rw0_wd_in[70]
  PIN rw0_wd_in[71]
    DIRECTION INPUT ;
    USE SIGNAL ;
    SHAPE ABUTMENT ;
    PORT
      LAYER M3 ;
      RECT 3.987 0.000 4.005 0.054 ;
    END
  END rw0_wd_in[71]
  PIN rw0_wd_in[72]
    DIRECTION INPUT ;
    USE SIGNAL ;
    SHAPE ABUTMENT ;
    PORT
      LAYER M3 ;
      RECT 4.527 0.000 4.545 0.054 ;
    END
  END rw0_wd_in[72]
  PIN rw0_wd_in[73]
    DIRECTION INPUT ;
    USE SIGNAL ;
    SHAPE ABUTMENT ;
    PORT
      LAYER M3 ;
      RECT 5.067 0.000 5.085 0.054 ;
    END
  END rw0_wd_in[73]
  PIN rw0_wd_in[74]
    DIRECTION INPUT ;
    USE SIGNAL ;
    SHAPE ABUTMENT ;
    PORT
      LAYER M3 ;
      RECT 5.607 0.000 5.625 0.054 ;
    END
  END rw0_wd_in[74]
  PIN rw0_wd_in[75]
    DIRECTION INPUT ;
    USE SIGNAL ;
    SHAPE ABUTMENT ;
    PORT
      LAYER M3 ;
      RECT 6.147 0.000 6.165 0.054 ;
    END
  END rw0_wd_in[75]
  PIN rw0_wd_in[76]
    DIRECTION INPUT ;
    USE SIGNAL ;
    SHAPE ABUTMENT ;
    PORT
      LAYER M3 ;
      RECT 6.687 0.000 6.705 0.054 ;
    END
  END rw0_wd_in[76]
  PIN rw0_wd_in[77]
    DIRECTION INPUT ;
    USE SIGNAL ;
    SHAPE ABUTMENT ;
    PORT
      LAYER M3 ;
      RECT 7.227 0.000 7.245 0.054 ;
    END
  END rw0_wd_in[77]
  PIN rw0_wd_in[78]
    DIRECTION INPUT ;
    USE SIGNAL ;
    SHAPE ABUTMENT ;
    PORT
      LAYER M3 ;
      RECT 7.767 0.000 7.785 0.054 ;
    END
  END rw0_wd_in[78]
  PIN rw0_wd_in[79]
    DIRECTION INPUT ;
    USE SIGNAL ;
    SHAPE ABUTMENT ;
    PORT
      LAYER M3 ;
      RECT 8.307 0.000 8.325 0.054 ;
    END
  END rw0_wd_in[79]
  PIN rw0_wd_in[80]
    DIRECTION INPUT ;
    USE SIGNAL ;
    SHAPE ABUTMENT ;
    PORT
      LAYER M3 ;
      RECT 8.847 0.000 8.865 0.054 ;
    END
  END rw0_wd_in[80]
  PIN rw0_wd_in[81]
    DIRECTION INPUT ;
    USE SIGNAL ;
    SHAPE ABUTMENT ;
    PORT
      LAYER M3 ;
      RECT 9.387 0.000 9.405 0.054 ;
    END
  END rw0_wd_in[81]
  PIN rw0_wd_in[82]
    DIRECTION INPUT ;
    USE SIGNAL ;
    SHAPE ABUTMENT ;
    PORT
      LAYER M3 ;
      RECT 9.927 0.000 9.945 0.054 ;
    END
  END rw0_wd_in[82]
  PIN rw0_wd_in[83]
    DIRECTION INPUT ;
    USE SIGNAL ;
    SHAPE ABUTMENT ;
    PORT
      LAYER M3 ;
      RECT 10.467 0.000 10.485 0.054 ;
    END
  END rw0_wd_in[83]
  PIN rw0_wd_in[84]
    DIRECTION INPUT ;
    USE SIGNAL ;
    SHAPE ABUTMENT ;
    PORT
      LAYER M3 ;
      RECT 11.007 0.000 11.025 0.054 ;
    END
  END rw0_wd_in[84]
  PIN rw0_wd_in[85]
    DIRECTION INPUT ;
    USE SIGNAL ;
    SHAPE ABUTMENT ;
    PORT
      LAYER M3 ;
      RECT 11.547 0.000 11.565 0.054 ;
    END
  END rw0_wd_in[85]
  PIN rw0_wd_in[86]
    DIRECTION INPUT ;
    USE SIGNAL ;
    SHAPE ABUTMENT ;
    PORT
      LAYER M3 ;
      RECT 12.087 0.000 12.105 0.054 ;
    END
  END rw0_wd_in[86]
  PIN rw0_wd_in[87]
    DIRECTION INPUT ;
    USE SIGNAL ;
    SHAPE ABUTMENT ;
    PORT
      LAYER M3 ;
      RECT 12.627 0.000 12.645 0.054 ;
    END
  END rw0_wd_in[87]
  PIN rw0_wd_in[88]
    DIRECTION INPUT ;
    USE SIGNAL ;
    SHAPE ABUTMENT ;
    PORT
      LAYER M3 ;
      RECT 13.167 0.000 13.185 0.054 ;
    END
  END rw0_wd_in[88]
  PIN rw0_wd_in[89]
    DIRECTION INPUT ;
    USE SIGNAL ;
    SHAPE ABUTMENT ;
    PORT
      LAYER M3 ;
      RECT 13.707 0.000 13.725 0.054 ;
    END
  END rw0_wd_in[89]
  PIN rw0_wd_in[90]
    DIRECTION INPUT ;
    USE SIGNAL ;
    SHAPE ABUTMENT ;
    PORT
      LAYER M3 ;
      RECT 14.247 0.000 14.265 0.054 ;
    END
  END rw0_wd_in[90]
  PIN rw0_wd_in[91]
    DIRECTION INPUT ;
    USE SIGNAL ;
    SHAPE ABUTMENT ;
    PORT
      LAYER M3 ;
      RECT 14.787 0.000 14.805 0.054 ;
    END
  END rw0_wd_in[91]
  PIN rw0_wd_in[92]
    DIRECTION INPUT ;
    USE SIGNAL ;
    SHAPE ABUTMENT ;
    PORT
      LAYER M3 ;
      RECT 15.327 0.000 15.345 0.054 ;
    END
  END rw0_wd_in[92]
  PIN rw0_wd_in[93]
    DIRECTION INPUT ;
    USE SIGNAL ;
    SHAPE ABUTMENT ;
    PORT
      LAYER M3 ;
      RECT 15.867 0.000 15.885 0.054 ;
    END
  END rw0_wd_in[93]
  PIN rw0_wd_in[94]
    DIRECTION INPUT ;
    USE SIGNAL ;
    SHAPE ABUTMENT ;
    PORT
      LAYER M3 ;
      RECT 16.407 0.000 16.425 0.054 ;
    END
  END rw0_wd_in[94]
  PIN rw0_wd_in[95]
    DIRECTION INPUT ;
    USE SIGNAL ;
    SHAPE ABUTMENT ;
    PORT
      LAYER M3 ;
      RECT 16.947 0.000 16.965 0.054 ;
    END
  END rw0_wd_in[95]
  PIN rw0_wd_in[96]
    DIRECTION INPUT ;
    USE SIGNAL ;
    SHAPE ABUTMENT ;
    PORT
      LAYER M3 ;
      RECT 17.487 0.000 17.505 0.054 ;
    END
  END rw0_wd_in[96]
  PIN rw0_wd_in[97]
    DIRECTION INPUT ;
    USE SIGNAL ;
    SHAPE ABUTMENT ;
    PORT
      LAYER M3 ;
      RECT 18.027 0.000 18.045 0.054 ;
    END
  END rw0_wd_in[97]
  PIN rw0_wd_in[98]
    DIRECTION INPUT ;
    USE SIGNAL ;
    SHAPE ABUTMENT ;
    PORT
      LAYER M3 ;
      RECT 18.567 0.000 18.585 0.054 ;
    END
  END rw0_wd_in[98]
  PIN rw0_wd_in[99]
    DIRECTION INPUT ;
    USE SIGNAL ;
    SHAPE ABUTMENT ;
    PORT
      LAYER M3 ;
      RECT 19.107 0.000 19.125 0.054 ;
    END
  END rw0_wd_in[99]
  PIN rw0_wd_in[100]
    DIRECTION INPUT ;
    USE SIGNAL ;
    SHAPE ABUTMENT ;
    PORT
      LAYER M3 ;
      RECT 19.647 0.000 19.665 0.054 ;
    END
  END rw0_wd_in[100]
  PIN rw0_wd_in[101]
    DIRECTION INPUT ;
    USE SIGNAL ;
    SHAPE ABUTMENT ;
    PORT
      LAYER M3 ;
      RECT 20.187 0.000 20.205 0.054 ;
    END
  END rw0_wd_in[101]
  PIN rw0_wd_in[102]
    DIRECTION INPUT ;
    USE SIGNAL ;
    SHAPE ABUTMENT ;
    PORT
      LAYER M3 ;
      RECT 20.727 0.000 20.745 0.054 ;
    END
  END rw0_wd_in[102]
  PIN rw0_wd_in[103]
    DIRECTION INPUT ;
    USE SIGNAL ;
    SHAPE ABUTMENT ;
    PORT
      LAYER M3 ;
      RECT 21.267 0.000 21.285 0.054 ;
    END
  END rw0_wd_in[103]
  PIN rw0_wd_in[104]
    DIRECTION INPUT ;
    USE SIGNAL ;
    SHAPE ABUTMENT ;
    PORT
      LAYER M3 ;
      RECT 21.807 0.000 21.825 0.054 ;
    END
  END rw0_wd_in[104]
  PIN rw0_wd_in[105]
    DIRECTION INPUT ;
    USE SIGNAL ;
    SHAPE ABUTMENT ;
    PORT
      LAYER M3 ;
      RECT 22.347 0.000 22.365 0.054 ;
    END
  END rw0_wd_in[105]
  PIN rw0_wd_in[106]
    DIRECTION INPUT ;
    USE SIGNAL ;
    SHAPE ABUTMENT ;
    PORT
      LAYER M3 ;
      RECT 22.887 0.000 22.905 0.054 ;
    END
  END rw0_wd_in[106]
  PIN rw0_wd_in[107]
    DIRECTION INPUT ;
    USE SIGNAL ;
    SHAPE ABUTMENT ;
    PORT
      LAYER M3 ;
      RECT 23.427 0.000 23.445 0.054 ;
    END
  END rw0_wd_in[107]
  PIN rw0_wd_in[108]
    DIRECTION INPUT ;
    USE SIGNAL ;
    SHAPE ABUTMENT ;
    PORT
      LAYER M3 ;
      RECT 23.967 0.000 23.985 0.054 ;
    END
  END rw0_wd_in[108]
  PIN rw0_wd_in[109]
    DIRECTION INPUT ;
    USE SIGNAL ;
    SHAPE ABUTMENT ;
    PORT
      LAYER M3 ;
      RECT 24.507 0.000 24.525 0.054 ;
    END
  END rw0_wd_in[109]
  PIN rw0_wd_in[110]
    DIRECTION INPUT ;
    USE SIGNAL ;
    SHAPE ABUTMENT ;
    PORT
      LAYER M3 ;
      RECT 25.047 0.000 25.065 0.054 ;
    END
  END rw0_wd_in[110]
  PIN rw0_wd_in[111]
    DIRECTION INPUT ;
    USE SIGNAL ;
    SHAPE ABUTMENT ;
    PORT
      LAYER M3 ;
      RECT 25.587 0.000 25.605 0.054 ;
    END
  END rw0_wd_in[111]
  PIN rw0_wd_in[112]
    DIRECTION INPUT ;
    USE SIGNAL ;
    SHAPE ABUTMENT ;
    PORT
      LAYER M3 ;
      RECT 26.127 0.000 26.145 0.054 ;
    END
  END rw0_wd_in[112]
  PIN rw0_wd_in[113]
    DIRECTION INPUT ;
    USE SIGNAL ;
    SHAPE ABUTMENT ;
    PORT
      LAYER M3 ;
      RECT 26.667 0.000 26.685 0.054 ;
    END
  END rw0_wd_in[113]
  PIN rw0_wd_in[114]
    DIRECTION INPUT ;
    USE SIGNAL ;
    SHAPE ABUTMENT ;
    PORT
      LAYER M3 ;
      RECT 27.207 0.000 27.225 0.054 ;
    END
  END rw0_wd_in[114]
  PIN rw0_wd_in[115]
    DIRECTION INPUT ;
    USE SIGNAL ;
    SHAPE ABUTMENT ;
    PORT
      LAYER M3 ;
      RECT 27.747 0.000 27.765 0.054 ;
    END
  END rw0_wd_in[115]
  PIN rw0_wd_in[116]
    DIRECTION INPUT ;
    USE SIGNAL ;
    SHAPE ABUTMENT ;
    PORT
      LAYER M3 ;
      RECT 28.287 0.000 28.305 0.054 ;
    END
  END rw0_wd_in[116]
  PIN rw0_wd_in[117]
    DIRECTION INPUT ;
    USE SIGNAL ;
    SHAPE ABUTMENT ;
    PORT
      LAYER M3 ;
      RECT 28.827 0.000 28.845 0.054 ;
    END
  END rw0_wd_in[117]
  PIN rw0_wd_in[118]
    DIRECTION INPUT ;
    USE SIGNAL ;
    SHAPE ABUTMENT ;
    PORT
      LAYER M3 ;
      RECT 29.367 0.000 29.385 0.054 ;
    END
  END rw0_wd_in[118]
  PIN rw0_wd_in[119]
    DIRECTION INPUT ;
    USE SIGNAL ;
    SHAPE ABUTMENT ;
    PORT
      LAYER M3 ;
      RECT 29.907 0.000 29.925 0.054 ;
    END
  END rw0_wd_in[119]
  PIN rw0_wd_in[120]
    DIRECTION INPUT ;
    USE SIGNAL ;
    SHAPE ABUTMENT ;
    PORT
      LAYER M3 ;
      RECT 30.447 0.000 30.465 0.054 ;
    END
  END rw0_wd_in[120]
  PIN rw0_wd_in[121]
    DIRECTION INPUT ;
    USE SIGNAL ;
    SHAPE ABUTMENT ;
    PORT
      LAYER M3 ;
      RECT 30.987 0.000 31.005 0.054 ;
    END
  END rw0_wd_in[121]
  PIN rw0_wd_in[122]
    DIRECTION INPUT ;
    USE SIGNAL ;
    SHAPE ABUTMENT ;
    PORT
      LAYER M3 ;
      RECT 31.527 0.000 31.545 0.054 ;
    END
  END rw0_wd_in[122]
  PIN rw0_wd_in[123]
    DIRECTION INPUT ;
    USE SIGNAL ;
    SHAPE ABUTMENT ;
    PORT
      LAYER M3 ;
      RECT 32.067 0.000 32.085 0.054 ;
    END
  END rw0_wd_in[123]
  PIN rw0_wd_in[124]
    DIRECTION INPUT ;
    USE SIGNAL ;
    SHAPE ABUTMENT ;
    PORT
      LAYER M3 ;
      RECT 32.607 0.000 32.625 0.054 ;
    END
  END rw0_wd_in[124]
  PIN rw0_wd_in[125]
    DIRECTION INPUT ;
    USE SIGNAL ;
    SHAPE ABUTMENT ;
    PORT
      LAYER M3 ;
      RECT 33.147 0.000 33.165 0.054 ;
    END
  END rw0_wd_in[125]
  PIN rw0_wd_in[126]
    DIRECTION INPUT ;
    USE SIGNAL ;
    SHAPE ABUTMENT ;
    PORT
      LAYER M3 ;
      RECT 33.687 0.000 33.705 0.054 ;
    END
  END rw0_wd_in[126]
  PIN rw0_wd_in[127]
    DIRECTION INPUT ;
    USE SIGNAL ;
    SHAPE ABUTMENT ;
    PORT
      LAYER M3 ;
      RECT 34.227 0.000 34.245 0.054 ;
    END
  END rw0_wd_in[127]
  PIN rw0_rd_out[0]
    DIRECTION OUTPUT ;
    USE SIGNAL ;
    SHAPE ABUTMENT ;
    PORT
      LAYER M3 ;
      RECT 34.767 0.000 34.785 0.054 ;
    END
  END rw0_rd_out[0]
  PIN rw0_rd_out[1]
    DIRECTION OUTPUT ;
    USE SIGNAL ;
    SHAPE ABUTMENT ;
    PORT
      LAYER M3 ;
      RECT 35.307 0.000 35.325 0.054 ;
    END
  END rw0_rd_out[1]
  PIN rw0_rd_out[2]
    DIRECTION OUTPUT ;
    USE SIGNAL ;
    SHAPE ABUTMENT ;
    PORT
      LAYER M3 ;
      RECT 35.847 0.000 35.865 0.054 ;
    END
  END rw0_rd_out[2]
  PIN rw0_rd_out[3]
    DIRECTION OUTPUT ;
    USE SIGNAL ;
    SHAPE ABUTMENT ;
    PORT
      LAYER M3 ;
      RECT 36.387 0.000 36.405 0.054 ;
    END
  END rw0_rd_out[3]
  PIN rw0_rd_out[4]
    DIRECTION OUTPUT ;
    USE SIGNAL ;
    SHAPE ABUTMENT ;
    PORT
      LAYER M3 ;
      RECT 36.927 0.000 36.945 0.054 ;
    END
  END rw0_rd_out[4]
  PIN rw0_rd_out[5]
    DIRECTION OUTPUT ;
    USE SIGNAL ;
    SHAPE ABUTMENT ;
    PORT
      LAYER M3 ;
      RECT 37.467 0.000 37.485 0.054 ;
    END
  END rw0_rd_out[5]
  PIN rw0_rd_out[6]
    DIRECTION OUTPUT ;
    USE SIGNAL ;
    SHAPE ABUTMENT ;
    PORT
      LAYER M3 ;
      RECT 38.007 0.000 38.025 0.054 ;
    END
  END rw0_rd_out[6]
  PIN rw0_rd_out[7]
    DIRECTION OUTPUT ;
    USE SIGNAL ;
    SHAPE ABUTMENT ;
    PORT
      LAYER M3 ;
      RECT 38.547 0.000 38.565 0.054 ;
    END
  END rw0_rd_out[7]
  PIN rw0_rd_out[8]
    DIRECTION OUTPUT ;
    USE SIGNAL ;
    SHAPE ABUTMENT ;
    PORT
      LAYER M3 ;
      RECT 39.087 0.000 39.105 0.054 ;
    END
  END rw0_rd_out[8]
  PIN rw0_rd_out[9]
    DIRECTION OUTPUT ;
    USE SIGNAL ;
    SHAPE ABUTMENT ;
    PORT
      LAYER M3 ;
      RECT 39.627 0.000 39.645 0.054 ;
    END
  END rw0_rd_out[9]
  PIN rw0_rd_out[10]
    DIRECTION OUTPUT ;
    USE SIGNAL ;
    SHAPE ABUTMENT ;
    PORT
      LAYER M3 ;
      RECT 40.167 0.000 40.185 0.054 ;
    END
  END rw0_rd_out[10]
  PIN rw0_rd_out[11]
    DIRECTION OUTPUT ;
    USE SIGNAL ;
    SHAPE ABUTMENT ;
    PORT
      LAYER M3 ;
      RECT 40.707 0.000 40.725 0.054 ;
    END
  END rw0_rd_out[11]
  PIN rw0_rd_out[12]
    DIRECTION OUTPUT ;
    USE SIGNAL ;
    SHAPE ABUTMENT ;
    PORT
      LAYER M3 ;
      RECT 41.247 0.000 41.265 0.054 ;
    END
  END rw0_rd_out[12]
  PIN rw0_rd_out[13]
    DIRECTION OUTPUT ;
    USE SIGNAL ;
    SHAPE ABUTMENT ;
    PORT
      LAYER M3 ;
      RECT 41.787 0.000 41.805 0.054 ;
    END
  END rw0_rd_out[13]
  PIN rw0_rd_out[14]
    DIRECTION OUTPUT ;
    USE SIGNAL ;
    SHAPE ABUTMENT ;
    PORT
      LAYER M3 ;
      RECT 42.327 0.000 42.345 0.054 ;
    END
  END rw0_rd_out[14]
  PIN rw0_rd_out[15]
    DIRECTION OUTPUT ;
    USE SIGNAL ;
    SHAPE ABUTMENT ;
    PORT
      LAYER M3 ;
      RECT 42.867 0.000 42.885 0.054 ;
    END
  END rw0_rd_out[15]
  PIN rw0_rd_out[16]
    DIRECTION OUTPUT ;
    USE SIGNAL ;
    SHAPE ABUTMENT ;
    PORT
      LAYER M3 ;
      RECT 43.407 0.000 43.425 0.054 ;
    END
  END rw0_rd_out[16]
  PIN rw0_rd_out[17]
    DIRECTION OUTPUT ;
    USE SIGNAL ;
    SHAPE ABUTMENT ;
    PORT
      LAYER M3 ;
      RECT 43.947 0.000 43.965 0.054 ;
    END
  END rw0_rd_out[17]
  PIN rw0_rd_out[18]
    DIRECTION OUTPUT ;
    USE SIGNAL ;
    SHAPE ABUTMENT ;
    PORT
      LAYER M3 ;
      RECT 44.487 0.000 44.505 0.054 ;
    END
  END rw0_rd_out[18]
  PIN rw0_rd_out[19]
    DIRECTION OUTPUT ;
    USE SIGNAL ;
    SHAPE ABUTMENT ;
    PORT
      LAYER M3 ;
      RECT 45.027 0.000 45.045 0.054 ;
    END
  END rw0_rd_out[19]
  PIN rw0_rd_out[20]
    DIRECTION OUTPUT ;
    USE SIGNAL ;
    SHAPE ABUTMENT ;
    PORT
      LAYER M3 ;
      RECT 45.567 0.000 45.585 0.054 ;
    END
  END rw0_rd_out[20]
  PIN rw0_rd_out[21]
    DIRECTION OUTPUT ;
    USE SIGNAL ;
    SHAPE ABUTMENT ;
    PORT
      LAYER M3 ;
      RECT 46.107 0.000 46.125 0.054 ;
    END
  END rw0_rd_out[21]
  PIN rw0_rd_out[22]
    DIRECTION OUTPUT ;
    USE SIGNAL ;
    SHAPE ABUTMENT ;
    PORT
      LAYER M3 ;
      RECT 46.647 0.000 46.665 0.054 ;
    END
  END rw0_rd_out[22]
  PIN rw0_rd_out[23]
    DIRECTION OUTPUT ;
    USE SIGNAL ;
    SHAPE ABUTMENT ;
    PORT
      LAYER M3 ;
      RECT 47.187 0.000 47.205 0.054 ;
    END
  END rw0_rd_out[23]
  PIN rw0_rd_out[24]
    DIRECTION OUTPUT ;
    USE SIGNAL ;
    SHAPE ABUTMENT ;
    PORT
      LAYER M3 ;
      RECT 47.727 0.000 47.745 0.054 ;
    END
  END rw0_rd_out[24]
  PIN rw0_rd_out[25]
    DIRECTION OUTPUT ;
    USE SIGNAL ;
    SHAPE ABUTMENT ;
    PORT
      LAYER M3 ;
      RECT 48.267 0.000 48.285 0.054 ;
    END
  END rw0_rd_out[25]
  PIN rw0_rd_out[26]
    DIRECTION OUTPUT ;
    USE SIGNAL ;
    SHAPE ABUTMENT ;
    PORT
      LAYER M3 ;
      RECT 48.807 0.000 48.825 0.054 ;
    END
  END rw0_rd_out[26]
  PIN rw0_rd_out[27]
    DIRECTION OUTPUT ;
    USE SIGNAL ;
    SHAPE ABUTMENT ;
    PORT
      LAYER M3 ;
      RECT 49.347 0.000 49.365 0.054 ;
    END
  END rw0_rd_out[27]
  PIN rw0_rd_out[28]
    DIRECTION OUTPUT ;
    USE SIGNAL ;
    SHAPE ABUTMENT ;
    PORT
      LAYER M3 ;
      RECT 49.887 0.000 49.905 0.054 ;
    END
  END rw0_rd_out[28]
  PIN rw0_rd_out[29]
    DIRECTION OUTPUT ;
    USE SIGNAL ;
    SHAPE ABUTMENT ;
    PORT
      LAYER M3 ;
      RECT 50.427 0.000 50.445 0.054 ;
    END
  END rw0_rd_out[29]
  PIN rw0_rd_out[30]
    DIRECTION OUTPUT ;
    USE SIGNAL ;
    SHAPE ABUTMENT ;
    PORT
      LAYER M3 ;
      RECT 50.967 0.000 50.985 0.054 ;
    END
  END rw0_rd_out[30]
  PIN rw0_rd_out[31]
    DIRECTION OUTPUT ;
    USE SIGNAL ;
    SHAPE ABUTMENT ;
    PORT
      LAYER M3 ;
      RECT 51.507 0.000 51.525 0.054 ;
    END
  END rw0_rd_out[31]
  PIN rw0_rd_out[32]
    DIRECTION OUTPUT ;
    USE SIGNAL ;
    SHAPE ABUTMENT ;
    PORT
      LAYER M3 ;
      RECT 52.047 0.000 52.065 0.054 ;
    END
  END rw0_rd_out[32]
  PIN rw0_rd_out[33]
    DIRECTION OUTPUT ;
    USE SIGNAL ;
    SHAPE ABUTMENT ;
    PORT
      LAYER M3 ;
      RECT 52.587 0.000 52.605 0.054 ;
    END
  END rw0_rd_out[33]
  PIN rw0_rd_out[34]
    DIRECTION OUTPUT ;
    USE SIGNAL ;
    SHAPE ABUTMENT ;
    PORT
      LAYER M3 ;
      RECT 53.127 0.000 53.145 0.054 ;
    END
  END rw0_rd_out[34]
  PIN rw0_rd_out[35]
    DIRECTION OUTPUT ;
    USE SIGNAL ;
    SHAPE ABUTMENT ;
    PORT
      LAYER M3 ;
      RECT 53.667 0.000 53.685 0.054 ;
    END
  END rw0_rd_out[35]
  PIN rw0_rd_out[36]
    DIRECTION OUTPUT ;
    USE SIGNAL ;
    SHAPE ABUTMENT ;
    PORT
      LAYER M3 ;
      RECT 54.207 0.000 54.225 0.054 ;
    END
  END rw0_rd_out[36]
  PIN rw0_rd_out[37]
    DIRECTION OUTPUT ;
    USE SIGNAL ;
    SHAPE ABUTMENT ;
    PORT
      LAYER M3 ;
      RECT 54.747 0.000 54.765 0.054 ;
    END
  END rw0_rd_out[37]
  PIN rw0_rd_out[38]
    DIRECTION OUTPUT ;
    USE SIGNAL ;
    SHAPE ABUTMENT ;
    PORT
      LAYER M3 ;
      RECT 55.287 0.000 55.305 0.054 ;
    END
  END rw0_rd_out[38]
  PIN rw0_rd_out[39]
    DIRECTION OUTPUT ;
    USE SIGNAL ;
    SHAPE ABUTMENT ;
    PORT
      LAYER M3 ;
      RECT 55.827 0.000 55.845 0.054 ;
    END
  END rw0_rd_out[39]
  PIN rw0_rd_out[40]
    DIRECTION OUTPUT ;
    USE SIGNAL ;
    SHAPE ABUTMENT ;
    PORT
      LAYER M3 ;
      RECT 56.367 0.000 56.385 0.054 ;
    END
  END rw0_rd_out[40]
  PIN rw0_rd_out[41]
    DIRECTION OUTPUT ;
    USE SIGNAL ;
    SHAPE ABUTMENT ;
    PORT
      LAYER M3 ;
      RECT 56.907 0.000 56.925 0.054 ;
    END
  END rw0_rd_out[41]
  PIN rw0_rd_out[42]
    DIRECTION OUTPUT ;
    USE SIGNAL ;
    SHAPE ABUTMENT ;
    PORT
      LAYER M3 ;
      RECT 57.447 0.000 57.465 0.054 ;
    END
  END rw0_rd_out[42]
  PIN rw0_rd_out[43]
    DIRECTION OUTPUT ;
    USE SIGNAL ;
    SHAPE ABUTMENT ;
    PORT
      LAYER M3 ;
      RECT 57.987 0.000 58.005 0.054 ;
    END
  END rw0_rd_out[43]
  PIN rw0_rd_out[44]
    DIRECTION OUTPUT ;
    USE SIGNAL ;
    SHAPE ABUTMENT ;
    PORT
      LAYER M3 ;
      RECT 58.527 0.000 58.545 0.054 ;
    END
  END rw0_rd_out[44]
  PIN rw0_rd_out[45]
    DIRECTION OUTPUT ;
    USE SIGNAL ;
    SHAPE ABUTMENT ;
    PORT
      LAYER M3 ;
      RECT 59.067 0.000 59.085 0.054 ;
    END
  END rw0_rd_out[45]
  PIN rw0_rd_out[46]
    DIRECTION OUTPUT ;
    USE SIGNAL ;
    SHAPE ABUTMENT ;
    PORT
      LAYER M3 ;
      RECT 59.607 0.000 59.625 0.054 ;
    END
  END rw0_rd_out[46]
  PIN rw0_rd_out[47]
    DIRECTION OUTPUT ;
    USE SIGNAL ;
    SHAPE ABUTMENT ;
    PORT
      LAYER M3 ;
      RECT 60.147 0.000 60.165 0.054 ;
    END
  END rw0_rd_out[47]
  PIN rw0_rd_out[48]
    DIRECTION OUTPUT ;
    USE SIGNAL ;
    SHAPE ABUTMENT ;
    PORT
      LAYER M3 ;
      RECT 60.687 0.000 60.705 0.054 ;
    END
  END rw0_rd_out[48]
  PIN rw0_rd_out[49]
    DIRECTION OUTPUT ;
    USE SIGNAL ;
    SHAPE ABUTMENT ;
    PORT
      LAYER M3 ;
      RECT 61.227 0.000 61.245 0.054 ;
    END
  END rw0_rd_out[49]
  PIN rw0_rd_out[50]
    DIRECTION OUTPUT ;
    USE SIGNAL ;
    SHAPE ABUTMENT ;
    PORT
      LAYER M3 ;
      RECT 61.767 0.000 61.785 0.054 ;
    END
  END rw0_rd_out[50]
  PIN rw0_rd_out[51]
    DIRECTION OUTPUT ;
    USE SIGNAL ;
    SHAPE ABUTMENT ;
    PORT
      LAYER M3 ;
      RECT 62.307 0.000 62.325 0.054 ;
    END
  END rw0_rd_out[51]
  PIN rw0_rd_out[52]
    DIRECTION OUTPUT ;
    USE SIGNAL ;
    SHAPE ABUTMENT ;
    PORT
      LAYER M3 ;
      RECT 62.847 0.000 62.865 0.054 ;
    END
  END rw0_rd_out[52]
  PIN rw0_rd_out[53]
    DIRECTION OUTPUT ;
    USE SIGNAL ;
    SHAPE ABUTMENT ;
    PORT
      LAYER M3 ;
      RECT 63.387 0.000 63.405 0.054 ;
    END
  END rw0_rd_out[53]
  PIN rw0_rd_out[54]
    DIRECTION OUTPUT ;
    USE SIGNAL ;
    SHAPE ABUTMENT ;
    PORT
      LAYER M3 ;
      RECT 63.927 0.000 63.945 0.054 ;
    END
  END rw0_rd_out[54]
  PIN rw0_rd_out[55]
    DIRECTION OUTPUT ;
    USE SIGNAL ;
    SHAPE ABUTMENT ;
    PORT
      LAYER M3 ;
      RECT 64.467 0.000 64.485 0.054 ;
    END
  END rw0_rd_out[55]
  PIN rw0_rd_out[56]
    DIRECTION OUTPUT ;
    USE SIGNAL ;
    SHAPE ABUTMENT ;
    PORT
      LAYER M3 ;
      RECT 65.007 0.000 65.025 0.054 ;
    END
  END rw0_rd_out[56]
  PIN rw0_rd_out[57]
    DIRECTION OUTPUT ;
    USE SIGNAL ;
    SHAPE ABUTMENT ;
    PORT
      LAYER M3 ;
      RECT 65.547 0.000 65.565 0.054 ;
    END
  END rw0_rd_out[57]
  PIN rw0_rd_out[58]
    DIRECTION OUTPUT ;
    USE SIGNAL ;
    SHAPE ABUTMENT ;
    PORT
      LAYER M3 ;
      RECT 66.087 0.000 66.105 0.054 ;
    END
  END rw0_rd_out[58]
  PIN rw0_rd_out[59]
    DIRECTION OUTPUT ;
    USE SIGNAL ;
    SHAPE ABUTMENT ;
    PORT
      LAYER M3 ;
      RECT 66.627 0.000 66.645 0.054 ;
    END
  END rw0_rd_out[59]
  PIN rw0_rd_out[60]
    DIRECTION OUTPUT ;
    USE SIGNAL ;
    SHAPE ABUTMENT ;
    PORT
      LAYER M3 ;
      RECT 67.167 0.000 67.185 0.054 ;
    END
  END rw0_rd_out[60]
  PIN rw0_rd_out[61]
    DIRECTION OUTPUT ;
    USE SIGNAL ;
    SHAPE ABUTMENT ;
    PORT
      LAYER M3 ;
      RECT 67.707 0.000 67.725 0.054 ;
    END
  END rw0_rd_out[61]
  PIN rw0_rd_out[62]
    DIRECTION OUTPUT ;
    USE SIGNAL ;
    SHAPE ABUTMENT ;
    PORT
      LAYER M3 ;
      RECT 68.247 0.000 68.265 0.054 ;
    END
  END rw0_rd_out[62]
  PIN rw0_rd_out[63]
    DIRECTION OUTPUT ;
    USE SIGNAL ;
    SHAPE ABUTMENT ;
    PORT
      LAYER M3 ;
      RECT 68.787 0.000 68.805 0.054 ;
    END
  END rw0_rd_out[63]
  PIN rw0_rd_out[64]
    DIRECTION OUTPUT ;
    USE SIGNAL ;
    SHAPE ABUTMENT ;
    PORT
      LAYER M3 ;
      RECT 34.767 90.234 34.785 90.288 ;
    END
  END rw0_rd_out[64]
  PIN rw0_rd_out[65]
    DIRECTION OUTPUT ;
    USE SIGNAL ;
    SHAPE ABUTMENT ;
    PORT
      LAYER M3 ;
      RECT 35.307 90.234 35.325 90.288 ;
    END
  END rw0_rd_out[65]
  PIN rw0_rd_out[66]
    DIRECTION OUTPUT ;
    USE SIGNAL ;
    SHAPE ABUTMENT ;
    PORT
      LAYER M3 ;
      RECT 35.847 90.234 35.865 90.288 ;
    END
  END rw0_rd_out[66]
  PIN rw0_rd_out[67]
    DIRECTION OUTPUT ;
    USE SIGNAL ;
    SHAPE ABUTMENT ;
    PORT
      LAYER M3 ;
      RECT 36.387 90.234 36.405 90.288 ;
    END
  END rw0_rd_out[67]
  PIN rw0_rd_out[68]
    DIRECTION OUTPUT ;
    USE SIGNAL ;
    SHAPE ABUTMENT ;
    PORT
      LAYER M3 ;
      RECT 36.927 90.234 36.945 90.288 ;
    END
  END rw0_rd_out[68]
  PIN rw0_rd_out[69]
    DIRECTION OUTPUT ;
    USE SIGNAL ;
    SHAPE ABUTMENT ;
    PORT
      LAYER M3 ;
      RECT 37.467 90.234 37.485 90.288 ;
    END
  END rw0_rd_out[69]
  PIN rw0_rd_out[70]
    DIRECTION OUTPUT ;
    USE SIGNAL ;
    SHAPE ABUTMENT ;
    PORT
      LAYER M3 ;
      RECT 38.007 90.234 38.025 90.288 ;
    END
  END rw0_rd_out[70]
  PIN rw0_rd_out[71]
    DIRECTION OUTPUT ;
    USE SIGNAL ;
    SHAPE ABUTMENT ;
    PORT
      LAYER M3 ;
      RECT 38.547 90.234 38.565 90.288 ;
    END
  END rw0_rd_out[71]
  PIN rw0_rd_out[72]
    DIRECTION OUTPUT ;
    USE SIGNAL ;
    SHAPE ABUTMENT ;
    PORT
      LAYER M3 ;
      RECT 39.087 90.234 39.105 90.288 ;
    END
  END rw0_rd_out[72]
  PIN rw0_rd_out[73]
    DIRECTION OUTPUT ;
    USE SIGNAL ;
    SHAPE ABUTMENT ;
    PORT
      LAYER M3 ;
      RECT 39.627 90.234 39.645 90.288 ;
    END
  END rw0_rd_out[73]
  PIN rw0_rd_out[74]
    DIRECTION OUTPUT ;
    USE SIGNAL ;
    SHAPE ABUTMENT ;
    PORT
      LAYER M3 ;
      RECT 40.167 90.234 40.185 90.288 ;
    END
  END rw0_rd_out[74]
  PIN rw0_rd_out[75]
    DIRECTION OUTPUT ;
    USE SIGNAL ;
    SHAPE ABUTMENT ;
    PORT
      LAYER M3 ;
      RECT 40.707 90.234 40.725 90.288 ;
    END
  END rw0_rd_out[75]
  PIN rw0_rd_out[76]
    DIRECTION OUTPUT ;
    USE SIGNAL ;
    SHAPE ABUTMENT ;
    PORT
      LAYER M3 ;
      RECT 41.247 90.234 41.265 90.288 ;
    END
  END rw0_rd_out[76]
  PIN rw0_rd_out[77]
    DIRECTION OUTPUT ;
    USE SIGNAL ;
    SHAPE ABUTMENT ;
    PORT
      LAYER M3 ;
      RECT 41.787 90.234 41.805 90.288 ;
    END
  END rw0_rd_out[77]
  PIN rw0_rd_out[78]
    DIRECTION OUTPUT ;
    USE SIGNAL ;
    SHAPE ABUTMENT ;
    PORT
      LAYER M3 ;
      RECT 42.327 90.234 42.345 90.288 ;
    END
  END rw0_rd_out[78]
  PIN rw0_rd_out[79]
    DIRECTION OUTPUT ;
    USE SIGNAL ;
    SHAPE ABUTMENT ;
    PORT
      LAYER M3 ;
      RECT 42.867 90.234 42.885 90.288 ;
    END
  END rw0_rd_out[79]
  PIN rw0_rd_out[80]
    DIRECTION OUTPUT ;
    USE SIGNAL ;
    SHAPE ABUTMENT ;
    PORT
      LAYER M3 ;
      RECT 43.407 90.234 43.425 90.288 ;
    END
  END rw0_rd_out[80]
  PIN rw0_rd_out[81]
    DIRECTION OUTPUT ;
    USE SIGNAL ;
    SHAPE ABUTMENT ;
    PORT
      LAYER M3 ;
      RECT 43.947 90.234 43.965 90.288 ;
    END
  END rw0_rd_out[81]
  PIN rw0_rd_out[82]
    DIRECTION OUTPUT ;
    USE SIGNAL ;
    SHAPE ABUTMENT ;
    PORT
      LAYER M3 ;
      RECT 44.487 90.234 44.505 90.288 ;
    END
  END rw0_rd_out[82]
  PIN rw0_rd_out[83]
    DIRECTION OUTPUT ;
    USE SIGNAL ;
    SHAPE ABUTMENT ;
    PORT
      LAYER M3 ;
      RECT 45.027 90.234 45.045 90.288 ;
    END
  END rw0_rd_out[83]
  PIN rw0_rd_out[84]
    DIRECTION OUTPUT ;
    USE SIGNAL ;
    SHAPE ABUTMENT ;
    PORT
      LAYER M3 ;
      RECT 45.567 90.234 45.585 90.288 ;
    END
  END rw0_rd_out[84]
  PIN rw0_rd_out[85]
    DIRECTION OUTPUT ;
    USE SIGNAL ;
    SHAPE ABUTMENT ;
    PORT
      LAYER M3 ;
      RECT 46.107 90.234 46.125 90.288 ;
    END
  END rw0_rd_out[85]
  PIN rw0_rd_out[86]
    DIRECTION OUTPUT ;
    USE SIGNAL ;
    SHAPE ABUTMENT ;
    PORT
      LAYER M3 ;
      RECT 46.647 90.234 46.665 90.288 ;
    END
  END rw0_rd_out[86]
  PIN rw0_rd_out[87]
    DIRECTION OUTPUT ;
    USE SIGNAL ;
    SHAPE ABUTMENT ;
    PORT
      LAYER M3 ;
      RECT 47.187 90.234 47.205 90.288 ;
    END
  END rw0_rd_out[87]
  PIN rw0_rd_out[88]
    DIRECTION OUTPUT ;
    USE SIGNAL ;
    SHAPE ABUTMENT ;
    PORT
      LAYER M3 ;
      RECT 47.727 90.234 47.745 90.288 ;
    END
  END rw0_rd_out[88]
  PIN rw0_rd_out[89]
    DIRECTION OUTPUT ;
    USE SIGNAL ;
    SHAPE ABUTMENT ;
    PORT
      LAYER M3 ;
      RECT 48.267 90.234 48.285 90.288 ;
    END
  END rw0_rd_out[89]
  PIN rw0_rd_out[90]
    DIRECTION OUTPUT ;
    USE SIGNAL ;
    SHAPE ABUTMENT ;
    PORT
      LAYER M3 ;
      RECT 48.807 90.234 48.825 90.288 ;
    END
  END rw0_rd_out[90]
  PIN rw0_rd_out[91]
    DIRECTION OUTPUT ;
    USE SIGNAL ;
    SHAPE ABUTMENT ;
    PORT
      LAYER M3 ;
      RECT 49.347 90.234 49.365 90.288 ;
    END
  END rw0_rd_out[91]
  PIN rw0_rd_out[92]
    DIRECTION OUTPUT ;
    USE SIGNAL ;
    SHAPE ABUTMENT ;
    PORT
      LAYER M3 ;
      RECT 49.887 90.234 49.905 90.288 ;
    END
  END rw0_rd_out[92]
  PIN rw0_rd_out[93]
    DIRECTION OUTPUT ;
    USE SIGNAL ;
    SHAPE ABUTMENT ;
    PORT
      LAYER M3 ;
      RECT 50.427 90.234 50.445 90.288 ;
    END
  END rw0_rd_out[93]
  PIN rw0_rd_out[94]
    DIRECTION OUTPUT ;
    USE SIGNAL ;
    SHAPE ABUTMENT ;
    PORT
      LAYER M3 ;
      RECT 50.967 90.234 50.985 90.288 ;
    END
  END rw0_rd_out[94]
  PIN rw0_rd_out[95]
    DIRECTION OUTPUT ;
    USE SIGNAL ;
    SHAPE ABUTMENT ;
    PORT
      LAYER M3 ;
      RECT 51.507 90.234 51.525 90.288 ;
    END
  END rw0_rd_out[95]
  PIN rw0_rd_out[96]
    DIRECTION OUTPUT ;
    USE SIGNAL ;
    SHAPE ABUTMENT ;
    PORT
      LAYER M3 ;
      RECT 52.047 90.234 52.065 90.288 ;
    END
  END rw0_rd_out[96]
  PIN rw0_rd_out[97]
    DIRECTION OUTPUT ;
    USE SIGNAL ;
    SHAPE ABUTMENT ;
    PORT
      LAYER M3 ;
      RECT 52.587 90.234 52.605 90.288 ;
    END
  END rw0_rd_out[97]
  PIN rw0_rd_out[98]
    DIRECTION OUTPUT ;
    USE SIGNAL ;
    SHAPE ABUTMENT ;
    PORT
      LAYER M3 ;
      RECT 53.127 90.234 53.145 90.288 ;
    END
  END rw0_rd_out[98]
  PIN rw0_rd_out[99]
    DIRECTION OUTPUT ;
    USE SIGNAL ;
    SHAPE ABUTMENT ;
    PORT
      LAYER M3 ;
      RECT 53.667 90.234 53.685 90.288 ;
    END
  END rw0_rd_out[99]
  PIN rw0_rd_out[100]
    DIRECTION OUTPUT ;
    USE SIGNAL ;
    SHAPE ABUTMENT ;
    PORT
      LAYER M3 ;
      RECT 54.207 90.234 54.225 90.288 ;
    END
  END rw0_rd_out[100]
  PIN rw0_rd_out[101]
    DIRECTION OUTPUT ;
    USE SIGNAL ;
    SHAPE ABUTMENT ;
    PORT
      LAYER M3 ;
      RECT 54.747 90.234 54.765 90.288 ;
    END
  END rw0_rd_out[101]
  PIN rw0_rd_out[102]
    DIRECTION OUTPUT ;
    USE SIGNAL ;
    SHAPE ABUTMENT ;
    PORT
      LAYER M3 ;
      RECT 55.287 90.234 55.305 90.288 ;
    END
  END rw0_rd_out[102]
  PIN rw0_rd_out[103]
    DIRECTION OUTPUT ;
    USE SIGNAL ;
    SHAPE ABUTMENT ;
    PORT
      LAYER M3 ;
      RECT 55.827 90.234 55.845 90.288 ;
    END
  END rw0_rd_out[103]
  PIN rw0_rd_out[104]
    DIRECTION OUTPUT ;
    USE SIGNAL ;
    SHAPE ABUTMENT ;
    PORT
      LAYER M3 ;
      RECT 56.367 90.234 56.385 90.288 ;
    END
  END rw0_rd_out[104]
  PIN rw0_rd_out[105]
    DIRECTION OUTPUT ;
    USE SIGNAL ;
    SHAPE ABUTMENT ;
    PORT
      LAYER M3 ;
      RECT 56.907 90.234 56.925 90.288 ;
    END
  END rw0_rd_out[105]
  PIN rw0_rd_out[106]
    DIRECTION OUTPUT ;
    USE SIGNAL ;
    SHAPE ABUTMENT ;
    PORT
      LAYER M3 ;
      RECT 57.447 90.234 57.465 90.288 ;
    END
  END rw0_rd_out[106]
  PIN rw0_rd_out[107]
    DIRECTION OUTPUT ;
    USE SIGNAL ;
    SHAPE ABUTMENT ;
    PORT
      LAYER M3 ;
      RECT 57.987 90.234 58.005 90.288 ;
    END
  END rw0_rd_out[107]
  PIN rw0_rd_out[108]
    DIRECTION OUTPUT ;
    USE SIGNAL ;
    SHAPE ABUTMENT ;
    PORT
      LAYER M3 ;
      RECT 58.527 90.234 58.545 90.288 ;
    END
  END rw0_rd_out[108]
  PIN rw0_rd_out[109]
    DIRECTION OUTPUT ;
    USE SIGNAL ;
    SHAPE ABUTMENT ;
    PORT
      LAYER M3 ;
      RECT 59.067 90.234 59.085 90.288 ;
    END
  END rw0_rd_out[109]
  PIN rw0_rd_out[110]
    DIRECTION OUTPUT ;
    USE SIGNAL ;
    SHAPE ABUTMENT ;
    PORT
      LAYER M3 ;
      RECT 59.607 90.234 59.625 90.288 ;
    END
  END rw0_rd_out[110]
  PIN rw0_rd_out[111]
    DIRECTION OUTPUT ;
    USE SIGNAL ;
    SHAPE ABUTMENT ;
    PORT
      LAYER M3 ;
      RECT 60.147 90.234 60.165 90.288 ;
    END
  END rw0_rd_out[111]
  PIN rw0_rd_out[112]
    DIRECTION OUTPUT ;
    USE SIGNAL ;
    SHAPE ABUTMENT ;
    PORT
      LAYER M3 ;
      RECT 60.687 90.234 60.705 90.288 ;
    END
  END rw0_rd_out[112]
  PIN rw0_rd_out[113]
    DIRECTION OUTPUT ;
    USE SIGNAL ;
    SHAPE ABUTMENT ;
    PORT
      LAYER M3 ;
      RECT 61.227 90.234 61.245 90.288 ;
    END
  END rw0_rd_out[113]
  PIN rw0_rd_out[114]
    DIRECTION OUTPUT ;
    USE SIGNAL ;
    SHAPE ABUTMENT ;
    PORT
      LAYER M3 ;
      RECT 61.767 90.234 61.785 90.288 ;
    END
  END rw0_rd_out[114]
  PIN rw0_rd_out[115]
    DIRECTION OUTPUT ;
    USE SIGNAL ;
    SHAPE ABUTMENT ;
    PORT
      LAYER M3 ;
      RECT 62.307 90.234 62.325 90.288 ;
    END
  END rw0_rd_out[115]
  PIN rw0_rd_out[116]
    DIRECTION OUTPUT ;
    USE SIGNAL ;
    SHAPE ABUTMENT ;
    PORT
      LAYER M3 ;
      RECT 62.847 90.234 62.865 90.288 ;
    END
  END rw0_rd_out[116]
  PIN rw0_rd_out[117]
    DIRECTION OUTPUT ;
    USE SIGNAL ;
    SHAPE ABUTMENT ;
    PORT
      LAYER M3 ;
      RECT 63.387 90.234 63.405 90.288 ;
    END
  END rw0_rd_out[117]
  PIN rw0_rd_out[118]
    DIRECTION OUTPUT ;
    USE SIGNAL ;
    SHAPE ABUTMENT ;
    PORT
      LAYER M3 ;
      RECT 63.927 90.234 63.945 90.288 ;
    END
  END rw0_rd_out[118]
  PIN rw0_rd_out[119]
    DIRECTION OUTPUT ;
    USE SIGNAL ;
    SHAPE ABUTMENT ;
    PORT
      LAYER M3 ;
      RECT 64.467 90.234 64.485 90.288 ;
    END
  END rw0_rd_out[119]
  PIN rw0_rd_out[120]
    DIRECTION OUTPUT ;
    USE SIGNAL ;
    SHAPE ABUTMENT ;
    PORT
      LAYER M3 ;
      RECT 65.007 90.234 65.025 90.288 ;
    END
  END rw0_rd_out[120]
  PIN rw0_rd_out[121]
    DIRECTION OUTPUT ;
    USE SIGNAL ;
    SHAPE ABUTMENT ;
    PORT
      LAYER M3 ;
      RECT 65.547 90.234 65.565 90.288 ;
    END
  END rw0_rd_out[121]
  PIN rw0_rd_out[122]
    DIRECTION OUTPUT ;
    USE SIGNAL ;
    SHAPE ABUTMENT ;
    PORT
      LAYER M3 ;
      RECT 66.087 90.234 66.105 90.288 ;
    END
  END rw0_rd_out[122]
  PIN rw0_rd_out[123]
    DIRECTION OUTPUT ;
    USE SIGNAL ;
    SHAPE ABUTMENT ;
    PORT
      LAYER M3 ;
      RECT 66.627 90.234 66.645 90.288 ;
    END
  END rw0_rd_out[123]
  PIN rw0_rd_out[124]
    DIRECTION OUTPUT ;
    USE SIGNAL ;
    SHAPE ABUTMENT ;
    PORT
      LAYER M3 ;
      RECT 67.167 90.234 67.185 90.288 ;
    END
  END rw0_rd_out[124]
  PIN rw0_rd_out[125]
    DIRECTION OUTPUT ;
    USE SIGNAL ;
    SHAPE ABUTMENT ;
    PORT
      LAYER M3 ;
      RECT 67.707 90.234 67.725 90.288 ;
    END
  END rw0_rd_out[125]
  PIN rw0_rd_out[126]
    DIRECTION OUTPUT ;
    USE SIGNAL ;
    SHAPE ABUTMENT ;
    PORT
      LAYER M3 ;
      RECT 68.247 90.234 68.265 90.288 ;
    END
  END rw0_rd_out[126]
  PIN rw0_rd_out[127]
    DIRECTION OUTPUT ;
    USE SIGNAL ;
    SHAPE ABUTMENT ;
    PORT
      LAYER M3 ;
      RECT 68.787 90.234 68.805 90.288 ;
    END
  END rw0_rd_out[127]
  PIN rw0_addr_in[0]
    DIRECTION INPUT ;
    USE SIGNAL ;
    SHAPE ABUTMENT ;
    PORT
      LAYER M4 ;
      RECT 0.000 83.220 0.072 83.244 ;
    END
  END rw0_addr_in[0]
  PIN rw0_addr_in[1]
    DIRECTION INPUT ;
    USE SIGNAL ;
    SHAPE ABUTMENT ;
    PORT
      LAYER M4 ;
      RECT 0.000 84.516 0.072 84.540 ;
    END
  END rw0_addr_in[1]
  PIN rw0_addr_in[2]
    DIRECTION INPUT ;
    USE SIGNAL ;
    SHAPE ABUTMENT ;
    PORT
      LAYER M4 ;
      RECT 0.000 85.812 0.072 85.836 ;
    END
  END rw0_addr_in[2]
  PIN rw0_addr_in[3]
    DIRECTION INPUT ;
    USE SIGNAL ;
    SHAPE ABUTMENT ;
    PORT
      LAYER M4 ;
      RECT 0.000 87.108 0.072 87.132 ;
    END
  END rw0_addr_in[3]
  PIN rw0_addr_in[4]
    DIRECTION INPUT ;
    USE SIGNAL ;
    SHAPE ABUTMENT ;
    PORT
      LAYER M4 ;
      RECT 72.159 83.220 72.231 83.244 ;
    END
  END rw0_addr_in[4]
  PIN rw0_addr_in[5]
    DIRECTION INPUT ;
    USE SIGNAL ;
    SHAPE ABUTMENT ;
    PORT
      LAYER M4 ;
      RECT 72.159 84.516 72.231 84.540 ;
    END
  END rw0_addr_in[5]
  PIN rw0_addr_in[6]
    DIRECTION INPUT ;
    USE SIGNAL ;
    SHAPE ABUTMENT ;
    PORT
      LAYER M4 ;
      RECT 72.159 85.812 72.231 85.836 ;
    END
  END rw0_addr_in[6]
  PIN rw0_addr_in[7]
    DIRECTION INPUT ;
    USE SIGNAL ;
    SHAPE ABUTMENT ;
    PORT
      LAYER M4 ;
      RECT 72.159 87.108 72.231 87.132 ;
    END
  END rw0_addr_in[7]
  PIN rw0_we_in
    DIRECTION INPUT ;
    USE SIGNAL ;
    SHAPE ABUTMENT ;
    PORT
      LAYER M3 ;
      RECT 69.327 90.234 69.345 90.288 ;
    END
  END rw0_we_in
  PIN rw0_ce_in
    DIRECTION INPUT ;
    USE SIGNAL ;
    SHAPE ABUTMENT ;
    PORT
      LAYER M3 ;
      RECT 69.867 90.234 69.885 90.288 ;
    END
  END rw0_ce_in
  PIN rw0_clk
    DIRECTION INPUT ;
    USE SIGNAL ;
    SHAPE ABUTMENT ;
    PORT
      LAYER M3 ;
      RECT 70.407 90.234 70.425 90.288 ;
    END
  END rw0_clk
  PIN VSS
    DIRECTION INOUT ;
    USE GROUND ;
    PORT
      LAYER M4 ;
      RECT 0.216 0.240 72.015 0.336 ;
      RECT 0.216 1.008 72.015 1.104 ;
      RECT 0.216 1.776 72.015 1.872 ;
      RECT 0.216 2.544 72.015 2.640 ;
      RECT 0.216 3.312 72.015 3.408 ;
      RECT 0.216 4.080 72.015 4.176 ;
      RECT 0.216 4.848 72.015 4.944 ;
      RECT 0.216 5.616 72.015 5.712 ;
      RECT 0.216 6.384 72.015 6.480 ;
      RECT 0.216 7.152 72.015 7.248 ;
      RECT 0.216 7.920 72.015 8.016 ;
      RECT 0.216 8.688 72.015 8.784 ;
      RECT 0.216 9.456 72.015 9.552 ;
      RECT 0.216 10.224 72.015 10.320 ;
      RECT 0.216 10.992 72.015 11.088 ;
      RECT 0.216 11.760 72.015 11.856 ;
      RECT 0.216 12.528 72.015 12.624 ;
      RECT 0.216 13.296 72.015 13.392 ;
      RECT 0.216 14.064 72.015 14.160 ;
      RECT 0.216 14.832 72.015 14.928 ;
      RECT 0.216 15.600 72.015 15.696 ;
      RECT 0.216 16.368 72.015 16.464 ;
      RECT 0.216 17.136 72.015 17.232 ;
      RECT 0.216 17.904 72.015 18.000 ;
      RECT 0.216 18.672 72.015 18.768 ;
      RECT 0.216 19.440 72.015 19.536 ;
      RECT 0.216 20.208 72.015 20.304 ;
      RECT 0.216 20.976 72.015 21.072 ;
      RECT 0.216 21.744 72.015 21.840 ;
      RECT 0.216 22.512 72.015 22.608 ;
      RECT 0.216 23.280 72.015 23.376 ;
      RECT 0.216 24.048 72.015 24.144 ;
      RECT 0.216 24.816 72.015 24.912 ;
      RECT 0.216 25.584 72.015 25.680 ;
      RECT 0.216 26.352 72.015 26.448 ;
      RECT 0.216 27.120 72.015 27.216 ;
      RECT 0.216 27.888 72.015 27.984 ;
      RECT 0.216 28.656 72.015 28.752 ;
      RECT 0.216 29.424 72.015 29.520 ;
      RECT 0.216 30.192 72.015 30.288 ;
      RECT 0.216 30.960 72.015 31.056 ;
      RECT 0.216 31.728 72.015 31.824 ;
      RECT 0.216 32.496 72.015 32.592 ;
      RECT 0.216 33.264 72.015 33.360 ;
      RECT 0.216 34.032 72.015 34.128 ;
      RECT 0.216 34.800 72.015 34.896 ;
      RECT 0.216 35.568 72.015 35.664 ;
      RECT 0.216 36.336 72.015 36.432 ;
      RECT 0.216 37.104 72.015 37.200 ;
      RECT 0.216 37.872 72.015 37.968 ;
      RECT 0.216 38.640 72.015 38.736 ;
      RECT 0.216 39.408 72.015 39.504 ;
      RECT 0.216 40.176 72.015 40.272 ;
      RECT 0.216 40.944 72.015 41.040 ;
      RECT 0.216 41.712 72.015 41.808 ;
      RECT 0.216 42.480 72.015 42.576 ;
      RECT 0.216 43.248 72.015 43.344 ;
      RECT 0.216 44.016 72.015 44.112 ;
      RECT 0.216 44.784 72.015 44.880 ;
      RECT 0.216 45.552 72.015 45.648 ;
      RECT 0.216 46.320 72.015 46.416 ;
      RECT 0.216 47.088 72.015 47.184 ;
      RECT 0.216 47.856 72.015 47.952 ;
      RECT 0.216 48.624 72.015 48.720 ;
      RECT 0.216 49.392 72.015 49.488 ;
      RECT 0.216 50.160 72.015 50.256 ;
      RECT 0.216 50.928 72.015 51.024 ;
      RECT 0.216 51.696 72.015 51.792 ;
      RECT 0.216 52.464 72.015 52.560 ;
      RECT 0.216 53.232 72.015 53.328 ;
      RECT 0.216 54.000 72.015 54.096 ;
      RECT 0.216 54.768 72.015 54.864 ;
      RECT 0.216 55.536 72.015 55.632 ;
      RECT 0.216 56.304 72.015 56.400 ;
      RECT 0.216 57.072 72.015 57.168 ;
      RECT 0.216 57.840 72.015 57.936 ;
      RECT 0.216 58.608 72.015 58.704 ;
      RECT 0.216 59.376 72.015 59.472 ;
      RECT 0.216 60.144 72.015 60.240 ;
      RECT 0.216 60.912 72.015 61.008 ;
      RECT 0.216 61.680 72.015 61.776 ;
      RECT 0.216 62.448 72.015 62.544 ;
      RECT 0.216 63.216 72.015 63.312 ;
      RECT 0.216 63.984 72.015 64.080 ;
      RECT 0.216 64.752 72.015 64.848 ;
      RECT 0.216 65.520 72.015 65.616 ;
      RECT 0.216 66.288 72.015 66.384 ;
      RECT 0.216 67.056 72.015 67.152 ;
      RECT 0.216 67.824 72.015 67.920 ;
      RECT 0.216 68.592 72.015 68.688 ;
      RECT 0.216 69.360 72.015 69.456 ;
      RECT 0.216 70.128 72.015 70.224 ;
      RECT 0.216 70.896 72.015 70.992 ;
      RECT 0.216 71.664 72.015 71.760 ;
      RECT 0.216 72.432 72.015 72.528 ;
      RECT 0.216 73.200 72.015 73.296 ;
      RECT 0.216 73.968 72.015 74.064 ;
      RECT 0.216 74.736 72.015 74.832 ;
      RECT 0.216 75.504 72.015 75.600 ;
      RECT 0.216 76.272 72.015 76.368 ;
      RECT 0.216 77.040 72.015 77.136 ;
      RECT 0.216 77.808 72.015 77.904 ;
      RECT 0.216 78.576 72.015 78.672 ;
      RECT 0.216 79.344 72.015 79.440 ;
      RECT 0.216 80.112 72.015 80.208 ;
      RECT 0.216 80.880 72.015 80.976 ;
      RECT 0.216 81.648 72.015 81.744 ;
      RECT 0.216 82.416 72.015 82.512 ;
      RECT 0.216 83.184 72.015 83.280 ;
      RECT 0.216 83.952 72.015 84.048 ;
      RECT 0.216 84.720 72.015 84.816 ;
      RECT 0.216 85.488 72.015 85.584 ;
      RECT 0.216 86.256 72.015 86.352 ;
      RECT 0.216 87.024 72.015 87.120 ;
      RECT 0.216 87.792 72.015 87.888 ;
      RECT 0.216 88.560 72.015 88.656 ;
      RECT 0.216 89.328 72.015 89.424 ;
      RECT 0.216 90.096 72.015 90.192 ;
    END
  END VSS
  PIN VDD
    DIRECTION INOUT ;
    USE POWER ;
    PORT
      LAYER M4 ;
      RECT 0.216 0.624 72.015 0.720 ;
      RECT 0.216 1.392 72.015 1.488 ;
      RECT 0.216 2.160 72.015 2.256 ;
      RECT 0.216 2.928 72.015 3.024 ;
      RECT 0.216 3.696 72.015 3.792 ;
      RECT 0.216 4.464 72.015 4.560 ;
      RECT 0.216 5.232 72.015 5.328 ;
      RECT 0.216 6.000 72.015 6.096 ;
      RECT 0.216 6.768 72.015 6.864 ;
      RECT 0.216 7.536 72.015 7.632 ;
      RECT 0.216 8.304 72.015 8.400 ;
      RECT 0.216 9.072 72.015 9.168 ;
      RECT 0.216 9.840 72.015 9.936 ;
      RECT 0.216 10.608 72.015 10.704 ;
      RECT 0.216 11.376 72.015 11.472 ;
      RECT 0.216 12.144 72.015 12.240 ;
      RECT 0.216 12.912 72.015 13.008 ;
      RECT 0.216 13.680 72.015 13.776 ;
      RECT 0.216 14.448 72.015 14.544 ;
      RECT 0.216 15.216 72.015 15.312 ;
      RECT 0.216 15.984 72.015 16.080 ;
      RECT 0.216 16.752 72.015 16.848 ;
      RECT 0.216 17.520 72.015 17.616 ;
      RECT 0.216 18.288 72.015 18.384 ;
      RECT 0.216 19.056 72.015 19.152 ;
      RECT 0.216 19.824 72.015 19.920 ;
      RECT 0.216 20.592 72.015 20.688 ;
      RECT 0.216 21.360 72.015 21.456 ;
      RECT 0.216 22.128 72.015 22.224 ;
      RECT 0.216 22.896 72.015 22.992 ;
      RECT 0.216 23.664 72.015 23.760 ;
      RECT 0.216 24.432 72.015 24.528 ;
      RECT 0.216 25.200 72.015 25.296 ;
      RECT 0.216 25.968 72.015 26.064 ;
      RECT 0.216 26.736 72.015 26.832 ;
      RECT 0.216 27.504 72.015 27.600 ;
      RECT 0.216 28.272 72.015 28.368 ;
      RECT 0.216 29.040 72.015 29.136 ;
      RECT 0.216 29.808 72.015 29.904 ;
      RECT 0.216 30.576 72.015 30.672 ;
      RECT 0.216 31.344 72.015 31.440 ;
      RECT 0.216 32.112 72.015 32.208 ;
      RECT 0.216 32.880 72.015 32.976 ;
      RECT 0.216 33.648 72.015 33.744 ;
      RECT 0.216 34.416 72.015 34.512 ;
      RECT 0.216 35.184 72.015 35.280 ;
      RECT 0.216 35.952 72.015 36.048 ;
      RECT 0.216 36.720 72.015 36.816 ;
      RECT 0.216 37.488 72.015 37.584 ;
      RECT 0.216 38.256 72.015 38.352 ;
      RECT 0.216 39.024 72.015 39.120 ;
      RECT 0.216 39.792 72.015 39.888 ;
      RECT 0.216 40.560 72.015 40.656 ;
      RECT 0.216 41.328 72.015 41.424 ;
      RECT 0.216 42.096 72.015 42.192 ;
      RECT 0.216 42.864 72.015 42.960 ;
      RECT 0.216 43.632 72.015 43.728 ;
      RECT 0.216 44.400 72.015 44.496 ;
      RECT 0.216 45.168 72.015 45.264 ;
      RECT 0.216 45.936 72.015 46.032 ;
      RECT 0.216 46.704 72.015 46.800 ;
      RECT 0.216 47.472 72.015 47.568 ;
      RECT 0.216 48.240 72.015 48.336 ;
      RECT 0.216 49.008 72.015 49.104 ;
      RECT 0.216 49.776 72.015 49.872 ;
      RECT 0.216 50.544 72.015 50.640 ;
      RECT 0.216 51.312 72.015 51.408 ;
      RECT 0.216 52.080 72.015 52.176 ;
      RECT 0.216 52.848 72.015 52.944 ;
      RECT 0.216 53.616 72.015 53.712 ;
      RECT 0.216 54.384 72.015 54.480 ;
      RECT 0.216 55.152 72.015 55.248 ;
      RECT 0.216 55.920 72.015 56.016 ;
      RECT 0.216 56.688 72.015 56.784 ;
      RECT 0.216 57.456 72.015 57.552 ;
      RECT 0.216 58.224 72.015 58.320 ;
      RECT 0.216 58.992 72.015 59.088 ;
      RECT 0.216 59.760 72.015 59.856 ;
      RECT 0.216 60.528 72.015 60.624 ;
      RECT 0.216 61.296 72.015 61.392 ;
      RECT 0.216 62.064 72.015 62.160 ;
      RECT 0.216 62.832 72.015 62.928 ;
      RECT 0.216 63.600 72.015 63.696 ;
      RECT 0.216 64.368 72.015 64.464 ;
      RECT 0.216 65.136 72.015 65.232 ;
      RECT 0.216 65.904 72.015 66.000 ;
      RECT 0.216 66.672 72.015 66.768 ;
      RECT 0.216 67.440 72.015 67.536 ;
      RECT 0.216 68.208 72.015 68.304 ;
      RECT 0.216 68.976 72.015 69.072 ;
      RECT 0.216 69.744 72.015 69.840 ;
      RECT 0.216 70.512 72.015 70.608 ;
      RECT 0.216 71.280 72.015 71.376 ;
      RECT 0.216 72.048 72.015 72.144 ;
      RECT 0.216 72.816 72.015 72.912 ;
      RECT 0.216 73.584 72.015 73.680 ;
      RECT 0.216 74.352 72.015 74.448 ;
      RECT 0.216 75.120 72.015 75.216 ;
      RECT 0.216 75.888 72.015 75.984 ;
      RECT 0.216 76.656 72.015 76.752 ;
      RECT 0.216 77.424 72.015 77.520 ;
      RECT 0.216 78.192 72.015 78.288 ;
      RECT 0.216 78.960 72.015 79.056 ;
      RECT 0.216 79.728 72.015 79.824 ;
      RECT 0.216 80.496 72.015 80.592 ;
      RECT 0.216 81.264 72.015 81.360 ;
      RECT 0.216 82.032 72.015 82.128 ;
      RECT 0.216 82.800 72.015 82.896 ;
      RECT 0.216 83.568 72.015 83.664 ;
      RECT 0.216 84.336 72.015 84.432 ;
      RECT 0.216 85.104 72.015 85.200 ;
      RECT 0.216 85.872 72.015 85.968 ;
      RECT 0.216 86.640 72.015 86.736 ;
      RECT 0.216 87.408 72.015 87.504 ;
      RECT 0.216 88.176 72.015 88.272 ;
      RECT 0.216 88.944 72.015 89.040 ;
      RECT 0.216 89.712 72.015 89.808 ;
    END
  END VDD
  OBS
    LAYER M1 ;
    RECT 0 0 72.231 90.288 ;
    LAYER M2 ;
    RECT 0 0 72.231 90.288 ;
    LAYER M3 ;
    RECT 0 0 72.231 90.288 ;
    LAYER M4 ;
    RECT 0 0 72.231 90.288 ;
  END
END fakeram_128x256_1rw

END LIBRARY
